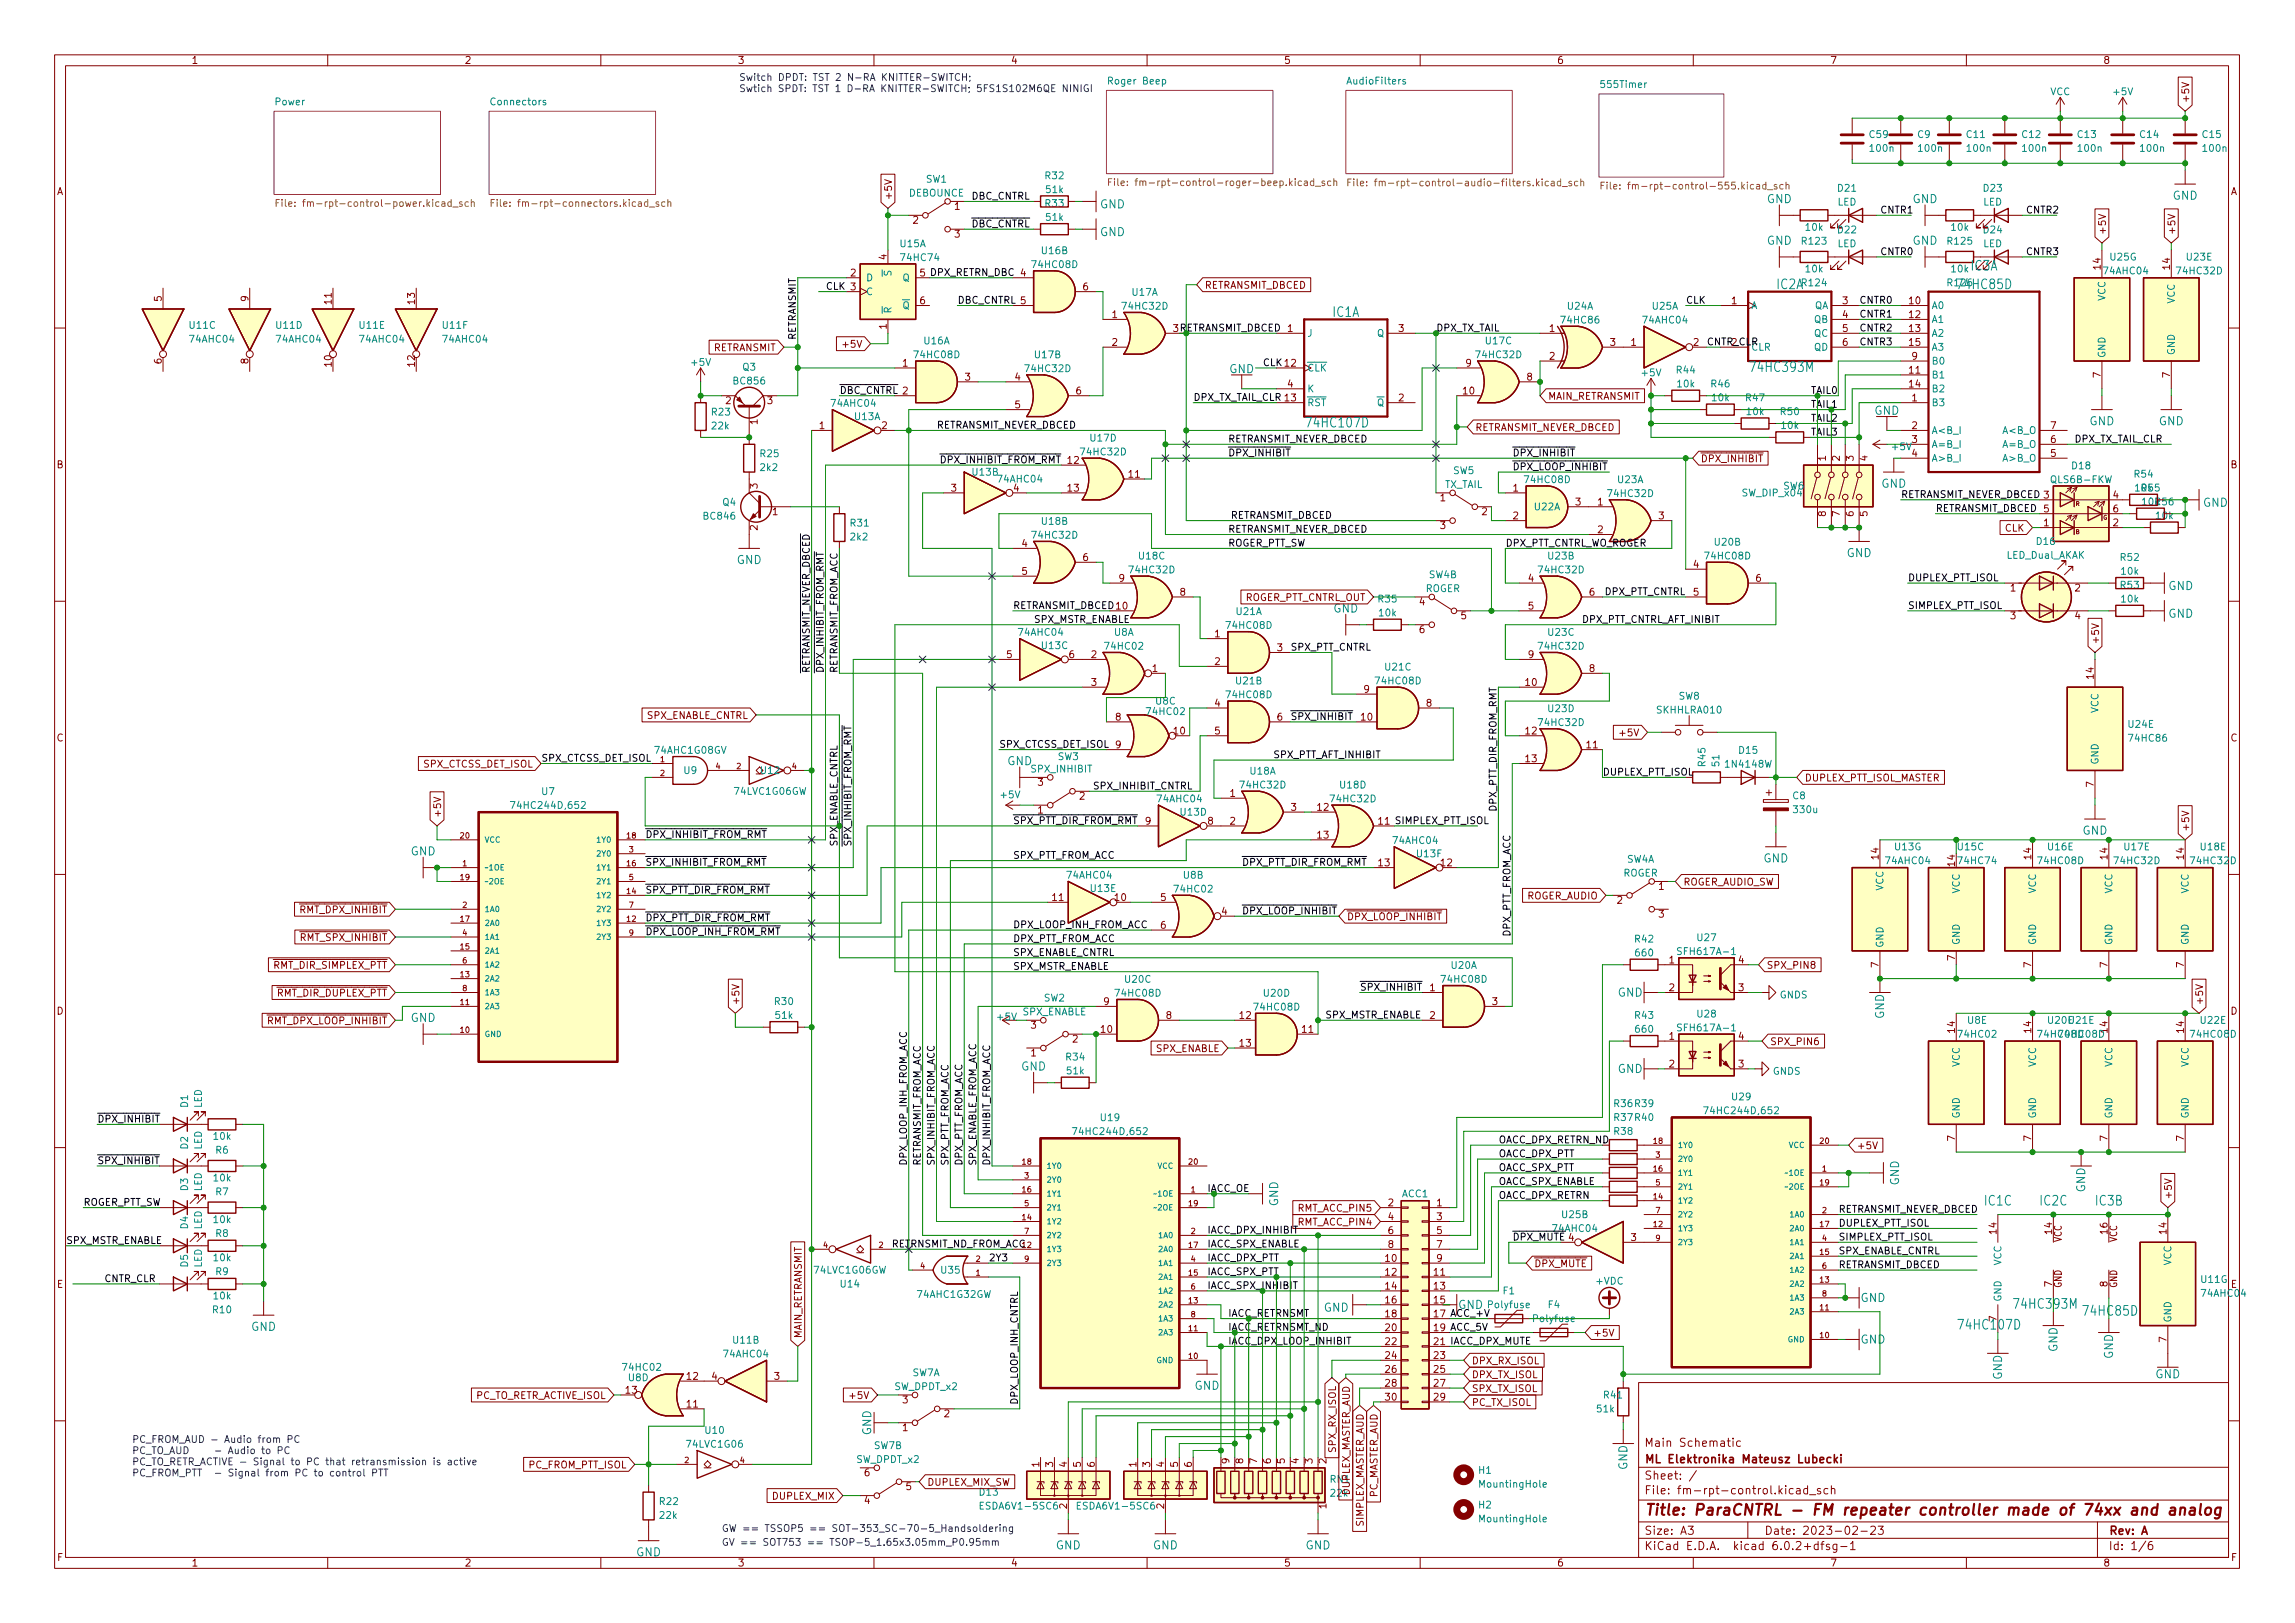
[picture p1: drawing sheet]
<svg xmlns="http://www.w3.org/2000/svg" width="420mm" height="297mm" viewBox="0 0 420 297" stroke-linecap="round" stroke-linejoin="round" font-family="sans-serif">
<defs><g id="words">
<text font-size="2.8" fill="#840000" x="301" y="277.3">Title: ParaCNTRL - FM repeater controller made of 74xx and analog</text>
<g font-size="2.5" fill="#008484">
<text x="325.3" y="52.9">IC2A</text>
<text x="358.6" y="52.9">74HC85D</text>
<text x="360.8" y="49.5">IC3A</text>
<text x="244" y="58">IC1A</text>
<text x="320.8" y="68.1">74HC393M</text>
<text x="239.6" y="78.2">74HC107D</text>
<text x="363.4" y="220.6">IC1C</text>
<text x="373.5" y="220.6">IC2C</text>
<text x="383.7" y="220.6">IC3B</text>
<text x="358.9" y="243.3">74HC107D</text>
<text x="381.7" y="240.8">74HC85D</text>
</g>
<text font-size="2.5" fill="#008400" x="369.1" y="239.5">74HC393M</text>
<g font-size="2.1" fill="#008484">
<text x="201.4" y="38.1">GND</text>
<text x="323.4" y="37.2">GND</text>
<text x="350.1" y="37.2">GND</text>
<text x="397.7" y="36.5">GND</text>
<text x="201.4" y="43.2">GND</text>
<text x="323.4" y="44.8">GND</text>
<text x="350.1" y="44.8">GND</text>
<text x="225" y="68.3">GND</text>
<text x="343.1" y="75.9">GND</text>
<text x="382.5" y="77.8">GND</text>
<text x="395.2" y="77.8">GND</text>
<text x="344.4" y="89.3">GND</text>
<text x="403.3" y="92.7">GND</text>
<text x="338" y="102">GND</text>
<text x="134.8" y="103.2">GND</text>
<text x="396.9" y="108">GND</text>
<text x="396.9" y="113.1">GND</text>
<text x="184.4" y="140">GND</text>
<text x="381.2" y="152.8">GND</text>
<text x="75.2" y="156.5">GND</text>
<text x="322.8" y="157.8">GND</text>
<text x="296.1" y="182.4">GND</text>
<text x="75.2" y="187">GND</text>
<text x="344.9" y="186.5" transform="rotate(-90 344.9 186.5)">GND</text>
<text x="186.9" y="195.9">GND</text>
<text x="296.1" y="196.4">GND</text>
<text x="234" y="220.8" transform="rotate(-90 234 220.8)">GND</text>
<text x="347.7" y="217" transform="rotate(-90 347.7 217)">GND</text>
<text x="381.7" y="218.3" transform="rotate(-90 381.7 218.3)">GND</text>
<text x="266.9" y="239.5">GND</text>
<text x="340.6" y="238.3">GND</text>
<text x="45.9" y="243.6">GND</text>
<text x="242.3" y="240.1">GND</text>
<text x="340.6" y="245.9">GND</text>
<text x="376.7" y="247.5" transform="rotate(-90 376.7 247.5)">GND</text>
<text x="386.8" y="248.7" transform="rotate(-90 386.8 248.7)">GND</text>
<text x="218.7" y="254.4">GND</text>
<text x="366.5" y="252.5" transform="rotate(-90 366.5 252.5)">GND</text>
<text x="394.6" y="252.2">GND</text>
<text x="159.5" y="262.7" transform="rotate(-90 159.5 262.7)">GND</text>
<text x="297.9" y="269.1" transform="rotate(-90 297.9 269.1)">GND</text>
<text x="116.4" y="284.8">GND</text>
<text x="193.3" y="283.6">GND</text>
<text x="211" y="283.6">GND</text>
<text x="239" y="283.6">GND</text>
</g>
<g font-size="2.1" fill="#840000">
<text x="244.1" y="112.1">GND</text>
<text x="301" y="267.8">ML Elektronika Mateusz Lubecki</text>
<text x="301" y="264.8">Main Schematic</text>
<text x="301" y="273.5">File: fm-rpt-control.kicad_sch</text>
<text x="301" y="270.8">Sheet: /</text>
<text x="301" y="280.9">Size: A3</text>
<text x="323" y="280.9">Date: 2023-02-23</text>
<text x="386" y="280.9">Rev: A</text>
<text x="301" y="283.7">KiCad E.D.A. kicad 6.0.2+dfsg-1</text>
<text x="386" y="283.7">Id: 1/6</text>
</g>
<g font-size="1.8" fill="#840000">
<text x="35" y="11.7">1</text>
<text x="85" y="11.7">2</text>
<text x="135" y="11.7">3</text>
<text x="185" y="11.7">4</text>
<text x="235" y="11.7">5</text>
<text x="285" y="11.7">6</text>
<text x="335" y="11.7">7</text>
<text x="385" y="11.7">8</text>
<text x="400.8" y="18.9" transform="rotate(-90 400.8 18.9)">+5V</text>
<text x="10.3" y="35.7">A</text>
<text x="408.3" y="35.7">A</text>
<text x="163.3" y="36.7" transform="rotate(-90 163.3 36.7)">+5V</text>
<text x="167.1" y="40.9">2</text>
<text x="174.8" y="38.4">1</text>
<text x="162.3" y="47.5" transform="rotate(-90 162.3 47.5)">4</text>
<text x="174.8" y="43.5">3</text>
<text x="385.5" y="43.1" transform="rotate(-90 385.5 43.1)">+5V</text>
<text x="398.2" y="43.1" transform="rotate(-90 398.2 43.1)">+5V</text>
<text x="155.7" y="50.6">2</text>
<text x="198.3" y="53.1">6</text>
<text x="220.5" y="52.8">RETRANSMIT_DBCED</text>
<text x="384.6" y="49.3" transform="rotate(-90 384.6 49.3)">14</text>
<text x="397.3" y="49.3" transform="rotate(-90 397.3 49.3)">14</text>
<text x="29.6" y="55.1" transform="rotate(-90 29.6 55.1)">5</text>
<text x="45.5" y="55.1" transform="rotate(-90 45.5 55.1)">9</text>
<text x="60.7" y="55.6" transform="rotate(-90 60.7 55.6)">11</text>
<text x="75.9" y="55.6" transform="rotate(-90 75.9 55.6)">13</text>
<text x="168.4" y="55.7">6</text>
<text x="203.6" y="58.2">1</text>
<text x="317" y="55.7">1</text>
<text x="337.3" y="55.7">3</text>
<text x="337.3" y="58.2">4</text>
<text x="349.5" y="55.7">10</text>
<text x="349.5" y="58.2">12</text>
<text x="130.5" y="64.3">RETRANSMIT</text>
<text x="154.8" y="63.6">+5V</text>
<text x="162.3" y="60.2" transform="rotate(-90 162.3 60.2)">1</text>
<text x="203.6" y="63.3">2</text>
<text x="256" y="60.7">3</text>
<text x="283.7" y="60.7">1</text>
<text x="283.7" y="65.8">2</text>
<text x="294.8" y="63.3">3</text>
<text x="298.6" y="63.3">1</text>
<text x="310" y="63.3">2</text>
<text x="337.3" y="60.7">5</text>
<text x="337.3" y="63.3">6</text>
<text x="349.5" y="60.7">13</text>
<text x="349.5" y="63.3">15</text>
<text x="350" y="65.8">9</text>
<text x="29.6" y="66.6" transform="rotate(-90 29.6 66.6)">6</text>
<text x="45.5" y="66.6" transform="rotate(-90 45.5 66.6)">8</text>
<text x="60.7" y="67.1" transform="rotate(-90 60.7 67.1)">10</text>
<text x="75.9" y="67.1" transform="rotate(-90 75.9 67.1)">12</text>
<text x="165.2" y="67.1">1</text>
<text x="176.7" y="69.6">3</text>
<text x="185.8" y="69.6">4</text>
<text x="235.7" y="70.9">4</text>
<text x="268.4" y="67.1">9</text>
<text x="279.5" y="69.6">8</text>
<text x="349.5" y="68.4">11</text>
<text x="349.5" y="70.9">14</text>
<text x="384.6" y="69.1" transform="rotate(-90 384.6 69.1)">7</text>
<text x="397.3" y="69.1" transform="rotate(-90 397.3 69.1)">7</text>
<text x="132.9" y="74">2</text>
<text x="138.7" y="77.7" transform="rotate(-90 138.7 77.7)">1</text>
<text x="140.5" y="74">3</text>
<text x="165.2" y="72.2">2</text>
<text x="185.8" y="74.7">5</text>
<text x="197" y="72.2">6</text>
<text x="256" y="73.4">2</text>
<text x="267.9" y="72.2">10</text>
<text x="283.4" y="73.2">MAIN_RETRANSMIT</text>
<text x="350" y="73.4">1</text>
<text x="150" y="78.5">1</text>
<text x="161.4" y="78.5">2</text>
<text x="270" y="78.9">RETRANSMIT_NEVER_DBCED</text>
<text x="350" y="78.5">2</text>
<text x="350" y="81.1">3</text>
<text x="350" y="83.6">4</text>
<text x="375.4" y="83.6">5</text>
<text x="375.4" y="81.1">6</text>
<text x="375.4" y="78.5">7</text>
<text x="10.3" y="85.7">B</text>
<text x="138.7" y="89.4" transform="rotate(-90 138.7 89.4)">3</text>
<text x="174.1" y="90">3</text>
<text x="185.6" y="90">4</text>
<text x="195.5" y="90">13</text>
<text x="206.7" y="87.4">11</text>
<text x="277" y="90">1</text>
<text x="311.3" y="84.6">~{DPX_INHIBIT}</text>
<text x="334.3" y="84.3" transform="rotate(-90 334.3 84.3)">1</text>
<text x="336.8" y="84.3" transform="rotate(-90 336.8 84.3)">2</text>
<text x="339.3" y="84.3" transform="rotate(-90 339.3 84.3)">3</text>
<text x="341.9" y="84.3" transform="rotate(-90 341.9 84.3)">4</text>
<text x="408.3" y="85.7">B</text>
<text x="141.4" y="94.3">1</text>
<text x="263.7" y="91.7">1</text>
<text x="271.3" y="94.3">2</text>
<text x="277" y="95">2</text>
<text x="288.4" y="92.5">3</text>
<text x="292.5" y="92.5">1</text>
<text x="303.7" y="95">3</text>
<text x="334.3" y="94.5" transform="rotate(-90 334.3 94.5)">8</text>
<text x="336.8" y="94.5" transform="rotate(-90 336.8 94.5)">7</text>
<text x="339.3" y="94.5" transform="rotate(-90 339.3 94.5)">6</text>
<text x="341.9" y="94.5" transform="rotate(-90 341.9 94.5)">5</text>
<text x="386.9" y="91.2">4</text>
<text x="386.9" y="93.8">6</text>
<text x="392.2" y="92.5">10kR56</text>
<text x="394.8" y="95">10k</text>
<text x="138.7" y="97" transform="rotate(-90 138.7 97)">2</text>
<text x="187.1" y="100.1">4</text>
<text x="263.7" y="96.8">3</text>
<text x="292.5" y="97.6">2</text>
<text x="367" y="97.3">CLK</text>
<text x="374.2" y="96.3">1</text>
<text x="386.9" y="96.3">2</text>
<text x="187.1" y="105.2">5</text>
<text x="198.3" y="102.7">6</text>
<text x="204.9" y="106.5">9</text>
<text x="279.8" y="106.5">4</text>
<text x="310" y="103.9">4</text>
<text x="321.5" y="106.5">6</text>
<text x="216" y="109">8</text>
<text x="227.5" y="110">ROGER_PTT_CNTRL_OUT</text>
<text x="259.9" y="110.8">4</text>
<text x="267.5" y="113.3">5</text>
<text x="279.8" y="111.5">5</text>
<text x="291" y="109">6</text>
<text x="310" y="109">5</text>
<text x="368.1" y="108.2">1</text>
<text x="368.1" y="113.3">3</text>
<text x="379.9" y="108.2">2</text>
<text x="379.9" y="113.3">4</text>
<text x="222.4" y="116.6">1</text>
<text x="233.8" y="119.2">3</text>
<text x="259.9" y="115.9">6</text>
<text x="384.3" y="118" transform="rotate(-90 384.3 118)">+5V</text>
<text x="184.3" y="120.4">5</text>
<text x="195.7" y="120.4">6</text>
<text x="199.8" y="120.4">2</text>
<text x="199.8" y="125.5">3</text>
<text x="211" y="123">1</text>
<text x="222.4" y="121.7">2</text>
<text x="279.3" y="125.5">10</text>
<text x="279.8" y="120.4">9</text>
<text x="291" y="123">8</text>
<text x="383.3" y="124.2" transform="rotate(-90 383.3 124.2)">14</text>
<text x="118.2" y="131.6">SPX_ENABLE_CNTRL</text>
<text x="204.2" y="131.9">8</text>
<text x="222.4" y="129.3">4</text>
<text x="233.8" y="131.9">6</text>
<text x="249.7" y="126.8">9</text>
<text x="261.1" y="129.3">8</text>
<text x="10.3" y="135.7">C</text>
<text x="204.2" y="136.9">9</text>
<text x="214.9" y="134.4">10</text>
<text x="222.4" y="134.4">5</text>
<text x="279.3" y="134.4">12</text>
<text x="290.5" y="136.9">11</text>
<text x="297" y="134.7">+5V</text>
<text x="408.3" y="135.7">C</text>
<text x="77.5" y="140.5">SPX_CTCSS_DET_ISOL</text>
<text x="190" y="143.8">3</text>
<text x="279.3" y="139.5">13</text>
<text x="330.4" y="143">DUPLEX_PTT_ISOL_MASTER</text>
<text x="80.7" y="149.7" transform="rotate(-90 80.7 149.7)">+5V</text>
<text x="190" y="148.9">1</text>
<text x="197.6" y="146.3">2</text>
<text x="225.2" y="145.8">1</text>
<text x="236.4" y="148.4">3</text>
<text x="241.2" y="148.4">12</text>
<text x="383.3" y="144" transform="rotate(-90 383.3 144)">7</text>
<text x="209.7" y="150.9">9</text>
<text x="221.1" y="150.9">8</text>
<text x="225.2" y="150.9">2</text>
<text x="241.2" y="153.5">13</text>
<text x="400.8" y="152.3" transform="rotate(-90 400.8 152.3)">+5V</text>
<text x="263.8" y="158.5">12</text>
<text x="343.9" y="157.2" transform="rotate(-90 343.9 157.2)">14</text>
<text x="357.9" y="158.5" transform="rotate(-90 357.9 158.5)">14</text>
<text x="371.9" y="157.2" transform="rotate(-90 371.9 157.2)">14</text>
<text x="385.8" y="157.2" transform="rotate(-90 385.8 157.2)">14</text>
<text x="399.8" y="157.2" transform="rotate(-90 399.8 157.2)">14</text>
<text x="53.8" y="167.1">~{RMT_DPX_INHIBIT}</text>
<text x="192.7" y="164.9">11</text>
<text x="204.1" y="164.9">10</text>
<text x="212.5" y="164.9">5</text>
<text x="223.7" y="167.4">4</text>
<text x="279.4" y="164.6">ROGER_AUDIO</text>
<text x="296.1" y="165.4">2</text>
<text x="303.7" y="162.9">1</text>
<text x="303.7" y="167.9">3</text>
<text x="308.1" y="162.1">ROGER_AUDIO_SW</text>
<text x="53.9" y="172.2">~{RMT_SPX_INHIBIT}</text>
<text x="212.5" y="170">6</text>
<text x="246.5" y="168.4">~{DPX_LOOP_INHIBIT}</text>
<text x="48.7" y="177.3">~{RMT_DIR_SIMPLEX_PTT}</text>
<text x="305.6" y="176.3">1</text>
<text x="318.3" y="176.3">4</text>
<text x="323.4" y="177.3">SPX_PIN8</text>
<text x="343.9" y="177.1" transform="rotate(-90 343.9 177.1)">7</text>
<text x="357.9" y="175.8" transform="rotate(-90 357.9 175.8)">7</text>
<text x="371.9" y="177.1" transform="rotate(-90 371.9 177.1)">7</text>
<text x="385.8" y="177.1" transform="rotate(-90 385.8 177.1)">7</text>
<text x="399.8" y="177.1" transform="rotate(-90 399.8 177.1)">7</text>
<text x="10.3" y="185.7">D</text>
<text x="49.2" y="182.4">~{RMT_DIR_DUPLEX_PTT}</text>
<text x="135.3" y="184" transform="rotate(-90 135.3 184)">+5V</text>
<text x="202.1" y="183.9">9</text>
<text x="273.2" y="183.9">3</text>
<text x="305.6" y="181.4">2</text>
<text x="318.3" y="181.4">3</text>
<text x="403.3" y="184" transform="rotate(-90 403.3 184)">+5V</text>
<text x="408.3" y="185.7">D</text>
<text x="47.8" y="187.5">~{RMT_DPX_LOOP_INHIBIT}</text>
<text x="188.7" y="188.3">3</text>
<text x="196.4" y="190.8">2</text>
<text x="201.6" y="189">10</text>
<text x="213.5" y="186.5">8</text>
<text x="227" y="186.5">12</text>
<text x="227" y="191.6">13</text>
<text x="238.4" y="189">11</text>
<text x="261.8" y="186.5">2</text>
<text x="305.6" y="190.3">1</text>
<text x="318.3" y="190.3">4</text>
<text x="324" y="191.3">SPX_PIN6</text>
<text x="357.9" y="189" transform="rotate(-90 357.9 189)">14</text>
<text x="371.9" y="189" transform="rotate(-90 371.9 189)">14</text>
<text x="385.8" y="189" transform="rotate(-90 385.8 189)">14</text>
<text x="399.8" y="189" transform="rotate(-90 399.8 189)">14</text>
<text x="188.7" y="193.3">1</text>
<text x="211.6" y="192.5">SPX_ENABLE</text>
<text x="305.6" y="195.4">2</text>
<text x="318.3" y="195.4">3</text>
<text x="357.9" y="208.8" transform="rotate(-90 357.9 208.8)">7</text>
<text x="371.9" y="208.8" transform="rotate(-90 371.9 208.8)">7</text>
<text x="385.8" y="208.8" transform="rotate(-90 385.8 208.8)">7</text>
<text x="399.8" y="208.8" transform="rotate(-90 399.8 208.8)">7</text>
<text x="339.9" y="210.3">+5V</text>
<text x="237.7" y="221.7">RMT_ACC_PIN5</text>
<text x="254.1" y="220.8">2</text>
<text x="263" y="220.8">1</text>
<text x="397.6" y="219.6" transform="rotate(-90 397.6 219.6)">+5V</text>
<text x="237.7" y="224.3">RMT_ACC_PIN4</text>
<text x="254.1" y="223.3">4</text>
<text x="254.1" y="225.8">6</text>
<text x="263" y="223.3">3</text>
<text x="263" y="225.8">5</text>
<text x="287.2" y="227.1">4</text>
<text x="298.6" y="227.1">3</text>
<text x="365.5" y="225.8" transform="rotate(-90 365.5 225.8)">14</text>
<text x="375.7" y="225.8" transform="rotate(-90 375.7 225.8)">14</text>
<text x="377.4" y="227.3" transform="rotate(-90 377.4 227.3)">VCC</text>
<text x="385.8" y="225.8" transform="rotate(-90 385.8 225.8)">16</text>
<text x="387.6" y="227.3" transform="rotate(-90 387.6 227.3)">VCC</text>
<text x="396.6" y="225.8" transform="rotate(-90 396.6 225.8)">14</text>
<text x="253.7" y="230.9">10</text>
<text x="253.7" y="233.5">12</text>
<text x="254.1" y="228.4">8</text>
<text x="262.5" y="233.5">11</text>
<text x="263" y="228.4">7</text>
<text x="263" y="230.9">9</text>
<text x="280.8" y="231.9">~{DPX_MUTE}</text>
<text x="10.4" y="235.7">E</text>
<text x="253.7" y="236">14</text>
<text x="253.7" y="238.5">16</text>
<text x="262.5" y="236">13</text>
<text x="262.5" y="238.5">15</text>
<text x="375.7" y="235.5" transform="rotate(-90 375.7 235.5)">7</text>
<text x="377.4" y="235.7" transform="rotate(-90 377.4 235.7)">GND</text>
<text x="385.8" y="235.5" transform="rotate(-90 385.8 235.5)">8</text>
<text x="387.6" y="235.7" transform="rotate(-90 387.6 235.7)">GND</text>
<text x="408.4" y="235.7">E</text>
<text x="146.8" y="245" transform="rotate(-90 146.8 245)">MAIN_RETRANSMIT</text>
<text x="253.7" y="241.1">18</text>
<text x="253.7" y="243.6">20</text>
<text x="291.6" y="244.6">+5V</text>
<text x="365.5" y="241.8" transform="rotate(-90 365.5 241.8)">7</text>
<text x="396.6" y="245.6" transform="rotate(-90 396.6 245.6)">7</text>
<text x="253.7" y="246.2">22</text>
<text x="253.7" y="248.7">24</text>
<text x="253.7" y="251.2">26</text>
<text x="262.5" y="248.7">23</text>
<text x="262.5" y="251.2">25</text>
<text x="269.4" y="249.7">DPX_RX_ISOL</text>
<text x="86.7" y="256">PC_TO_RETR_ACTIVE_ISOL</text>
<text x="114.6" y="255.1">13</text>
<text x="125.8" y="257.6">11</text>
<text x="125.8" y="252.5">12</text>
<text x="130.3" y="252.5">4</text>
<text x="141.7" y="252.5">3</text>
<text x="156" y="256">+5V</text>
<text x="165.2" y="256.8">3</text>
<text x="253.7" y="253.8">28</text>
<text x="253.7" y="256.3">30</text>
<text x="262.5" y="253.8">27</text>
<text x="262.5" y="256.3">29</text>
<text x="269.4" y="252.2">DPX_TX_ISOL</text>
<text x="269.4" y="254.8">SPX_TX_ISOL</text>
<text x="269.4" y="257.3">PC_TX_ISOL</text>
<text x="165.2" y="261.9">1</text>
<text x="172.9" y="259.4">2</text>
<text x="96.7" y="268.7">PC_FROM_PTT_ISOL</text>
<text x="190.2" y="268.5" transform="rotate(-90 190.2 268.5)">1</text>
<text x="192.8" y="268.5" transform="rotate(-90 192.8 268.5)">3</text>
<text x="195.3" y="268.5" transform="rotate(-90 195.3 268.5)">4</text>
<text x="197.9" y="268.5" transform="rotate(-90 197.9 268.5)">5</text>
<text x="200.4" y="268.5" transform="rotate(-90 200.4 268.5)">6</text>
<text x="208" y="268.5" transform="rotate(-90 208 268.5)">1</text>
<text x="210.6" y="268.5" transform="rotate(-90 210.6 268.5)">3</text>
<text x="213.1" y="268.5" transform="rotate(-90 213.1 268.5)">4</text>
<text x="215.6" y="268.5" transform="rotate(-90 215.6 268.5)">5</text>
<text x="218.2" y="268.5" transform="rotate(-90 218.2 268.5)">6</text>
<text x="225" y="267.9" transform="rotate(-90 225 267.9)">9</text>
<text x="227.6" y="267.9" transform="rotate(-90 227.6 267.9)">8</text>
<text x="230.1" y="267.9" transform="rotate(-90 230.1 267.9)">7</text>
<text x="232.7" y="267.9" transform="rotate(-90 232.7 267.9)">6</text>
<text x="235.2" y="267.9" transform="rotate(-90 235.2 267.9)">5</text>
<text x="237.7" y="267.9" transform="rotate(-90 237.7 267.9)">4</text>
<text x="240.3" y="267.9" transform="rotate(-90 240.3 267.9)">3</text>
<text x="242.8" y="267.9" transform="rotate(-90 242.8 267.9)">2</text>
<text x="244.6" y="265.7" transform="rotate(-90 244.6 265.7)">SPX_RX_ISOL</text>
<text x="141.6" y="274.4">DUPLEX_MIX</text>
<text x="158.3" y="275.2">4</text>
<text x="158.3" y="270.2">6</text>
<text x="165.9" y="272.7">5</text>
<text x="169.7" y="271.9">DUPLEX_MIX_SW</text>
<text x="179.4" y="273.7">D13</text>
<text x="197.2" y="273.7">D14</text>
<text x="243.5" y="271.4">RN1</text>
<text x="243.7" y="273.9">22k</text>
<text x="247.1" y="274" transform="rotate(-90 247.1 274)">DUPLEX_MASTER_AUD</text>
<text x="252.2" y="274.4" transform="rotate(-90 252.2 274.4)">PC_MASTER_AUD</text>
<text x="195.3" y="276.1" transform="rotate(-90 195.3 276.1)">2</text>
<text x="213.1" y="276.1" transform="rotate(-90 213.1 276.1)">2</text>
<text x="242.8" y="276.1" transform="rotate(-90 242.8 276.1)">1</text>
<text x="249.6" y="279.7" transform="rotate(-90 249.6 279.7)">SIMPLEX_MASTER_AUD</text>
<text x="10.4" y="285.7">F</text>
<text x="35" y="286.7">1</text>
<text x="85" y="286.7">2</text>
<text x="135" y="286.7">3</text>
<text x="185" y="286.7">4</text>
<text x="235" y="286.7">5</text>
<text x="285" y="286.7">6</text>
<text x="335" y="286.7">7</text>
<text x="385" y="286.7">8</text>
<text x="408.4" y="285.7">F</text>
</g>
<g font-size="1.8" fill="#0000c2">
<text x="135.3" y="14.8">Switch DPDT: TST 2 N-RA KNITTER-SWITCH;</text>
<text x="135.3" y="16.8">Swtich SPDT: TST 1 D-RA KNITTER-SWITCH; 5FS1S102M6QE NINIGI</text>
<text x="24.1" y="264.1">PC_FROM_AUD - Audio from PC</text>
<text x="24.1" y="266.1">PC_TO_AUD - Audio to PC</text>
<text x="24.1" y="268.2">PC_TO_RETR_ACTIVE - Signal to PC that retransmission is active</text>
<text x="24.1" y="270.2">PC_FROM_PTT - Signal from PC to control PTT</text>
<text x="132.1" y="280.4">GW == TSSOP5 == SOT-353_SC-70-5_Handsoldering</text>
<text x="132.1" y="282.9">GV == SOT753 == TSOP-5_1.65x3.05mm_P0.95mm</text>
</g>
<g font-size="1.8" fill="#008484">
<text x="203.2" y="15.4">Roger Beep</text>
<text x="246.9" y="15.4">AudioFilters</text>
<text x="293.3" y="16.1">555Timer</text>
<text x="375.3" y="17.4">VCC</text>
<text x="387" y="17.4">+5V</text>
<text x="50.4" y="19.3">Power</text>
<text x="90" y="19.3">Connectors</text>
<text x="342.3" y="25.2">C59</text>
<text x="342.5" y="27.8">100n</text>
<text x="351.1" y="25.2">C9</text>
<text x="351.4" y="27.8">100n</text>
<text x="360.1" y="25.2">C11</text>
<text x="360.2" y="27.8">100n</text>
<text x="370.3" y="25.2">C12</text>
<text x="370.4" y="27.8">100n</text>
<text x="380.4" y="25.2">C13</text>
<text x="380.6" y="27.8">100n</text>
<text x="391.8" y="25.2">C14</text>
<text x="392" y="27.8">100n</text>
<text x="403.3" y="25.2">C15</text>
<text x="403.4" y="27.8">100n</text>
<text x="166.4" y="36">DEBOUNCE</text>
<text x="169.5" y="33.4">SW1</text>
<text x="191.4" y="32.8">R32</text>
<text x="191.6" y="35.3">51k</text>
<text x="336.5" y="35.1">D21</text>
<text x="363.2" y="35.1">D23</text>
<text x="191.4" y="37.9">R33</text>
<text x="191.6" y="40.4">51k</text>
<text x="336.4" y="37.6">LED</text>
<text x="363" y="37.6">LED</text>
<text x="164.8" y="45.2">U15A</text>
<text x="165.1" y="47.8">74HC74</text>
<text x="190.8" y="46.5">U16B</text>
<text x="330" y="44.8">R123</text>
<text x="330.6" y="42.2">10k</text>
<text x="336.4" y="45.2">LED</text>
<text x="336.5" y="42.7">D22</text>
<text x="356.7" y="44.8">R125</text>
<text x="357.3" y="42.2">10k</text>
<text x="363" y="45.2">LED</text>
<text x="363.2" y="42.7">D24</text>
<text x="386.4" y="47.7">U25G</text>
<text x="400.4" y="47.7">U23E</text>
<text x="158.5" y="51.5">D</text>
<text x="165.2" y="51.5">Q</text>
<text x="189.2" y="49">74HC08D</text>
<text x="330" y="52.4">R124</text>
<text x="330.6" y="49.8">10k</text>
<text x="356.7" y="52.4">R126</text>
<text x="357.3" y="49.8">10k</text>
<text x="385.3" y="50.2">74AHC04</text>
<text x="398.7" y="50.2">74HC32D</text>
<text x="158.5" y="54">C</text>
<text x="163.2" y="57.4" transform="rotate(-90 163.2 57.4)">~{R}</text>
<text x="163.9" y="56.6">~{Q}</text>
<text x="205.7" y="56.7">74HC32D</text>
<text x="207.3" y="54.1">U17A</text>
<text x="286" y="59.2">74HC86</text>
<text x="287" y="56.7">U24A</text>
<text x="300.9" y="59.2">74AHC04</text>
<text x="302.5" y="56.7">U25A</text>
<text x="320.5" y="56.6">A</text>
<text x="332.1" y="56.6">QA</text>
<text x="332.1" y="59.1">QB</text>
<text x="353.6" y="56.6">A0</text>
<text x="353.6" y="59.1">A1</text>
<text x="385.4" y="55.1" transform="rotate(-90 385.4 55.1)">VCC</text>
<text x="398.1" y="55.6" transform="rotate(-90 398.1 55.6)">VCC</text>
<text x="34.7" y="60.2">U11C</text>
<text x="34.9" y="62.7">74AHC04</text>
<text x="50.6" y="60.2">U11D</text>
<text x="50.8" y="62.7">74AHC04</text>
<text x="65.8" y="60.2">U11E</text>
<text x="66" y="62.7">74AHC04</text>
<text x="81.1" y="60.2">U11F</text>
<text x="81.2" y="62.7">74AHC04</text>
<text x="167.6" y="65.5">74HC08D</text>
<text x="169.2" y="63">U16A</text>
<text x="189.5" y="65.6">U17B</text>
<text x="239.3" y="61.6">J</text>
<text x="252.1" y="61.6">Q</text>
<text x="270.4" y="65.5">74HC32D</text>
<text x="272.1" y="63">U17C</text>
<text x="332.1" y="61.6">QC</text>
<text x="332.1" y="64.2">QD</text>
<text x="353.6" y="61.6">A2</text>
<text x="353.6" y="64.2">A3</text>
<text x="385.4" y="65.6" transform="rotate(-90 385.4 65.6)">GND</text>
<text x="398.1" y="65.1" transform="rotate(-90 398.1 65.1)">GND</text>
<text x="126.7" y="66.9">+5V</text>
<text x="134.4" y="70.3">BC856</text>
<text x="136" y="67.8">Q3</text>
<text x="187.9" y="68.1">74HC32D</text>
<text x="239.3" y="68">~{CLK}</text>
<text x="239.3" y="71.8">K</text>
<text x="300.7" y="68.9">+5V</text>
<text x="307" y="68.3">R44</text>
<text x="307.1" y="70.9">10k</text>
<text x="313.3" y="70.9">R46</text>
<text x="353.6" y="69.3">B1</text>
<text x="353.6" y="71.8">B2</text>
<text x="353.6" y="66.7">B0</text>
<text x="130.4" y="76">R23</text>
<text x="152.3" y="74.4">74AHC04</text>
<text x="156.5" y="76.9">U13A</text>
<text x="239.3" y="74.3">~{RST}</text>
<text x="250.7" y="74.3">~{Q}</text>
<text x="313.5" y="73.4">10k</text>
<text x="319.7" y="73.4">R47</text>
<text x="319.8" y="76">10k</text>
<text x="326" y="76">R50</text>
<text x="353.6" y="74.3">B3</text>
<text x="130.4" y="78.6">22k</text>
<text x="139.2" y="83.7">R25</text>
<text x="198" y="83.3">74HC32D</text>
<text x="199.7" y="80.8">U17D</text>
<text x="326.2" y="78.5">10k</text>
<text x="346.5" y="82.4">+5V</text>
<text x="353.6" y="79.4">A&lt;B_I</text>
<text x="353.6" y="82">A=B_I</text>
<text x="366.9" y="82">A=B_O</text>
<text x="366.9" y="79.4">A&lt;B_O</text>
<text x="139.3" y="86.2">2k2</text>
<text x="178.1" y="87">U13B</text>
<text x="182.8" y="88.3">74AHC04</text>
<text x="264.4" y="89.3">TX_TAIL</text>
<text x="266.1" y="86.8">SW5</text>
<text x="279.3" y="88.4">74HC08D</text>
<text x="296.2" y="88.4">U23A</text>
<text x="326.5" y="89.6">SW6</text>
<text x="353.6" y="84.5">A&gt;B_I</text>
<text x="366.9" y="84.5">A&gt;B_O</text>
<text x="375.7" y="88.4">QLS6B-FKW</text>
<text x="379.4" y="85.9">D18</text>
<text x="390.8" y="87.4">R54</text>
<text x="391" y="89.9">10k</text>
<text x="128.9" y="95.1">BC846</text>
<text x="132.3" y="92.5">Q4</text>
<text x="280.9" y="93.4">U22A</text>
<text x="294.6" y="90.9">74HC32D</text>
<text x="319.1" y="90.8">SW_DIP_x04</text>
<text x="155.8" y="96.4">R31</text>
<text x="155.8" y="98.9">2k2</text>
<text x="189.2" y="98.6">74HC32D</text>
<text x="190.8" y="96">U18B</text>
<text x="314" y="99.8">U20B</text>
<text x="372.9" y="99.7">D16</text>
<text x="206.9" y="104.9">74HC32D</text>
<text x="208.6" y="102.4">U18C</text>
<text x="261.6" y="105.8">SW4B</text>
<text x="281.9" y="104.9">74HC32D</text>
<text x="283.5" y="102.4">U23B</text>
<text x="312.3" y="102.4">74HC08D</text>
<text x="367.3" y="102.3">LED_Dual_AKAK</text>
<text x="388.3" y="107.7">R53</text>
<text x="388.3" y="102.6">R52</text>
<text x="388.4" y="105.2">10k</text>
<text x="226.3" y="112.5">U21A</text>
<text x="252.4" y="110.3">R35</text>
<text x="252.5" y="112.8">10k</text>
<text x="260.9" y="108.3">ROGER</text>
<text x="388.4" y="110.3">10k</text>
<text x="186.6" y="116.3">74AHC04</text>
<text x="190.8" y="118.8">U13C</text>
<text x="202.5" y="118.9">74HC02</text>
<text x="204" y="116.4">U8A</text>
<text x="224.7" y="115.1">74HC08D</text>
<text x="281.9" y="118.9">74HC32D</text>
<text x="283.5" y="116.4">U23C</text>
<text x="226.3" y="125.2">U21B</text>
<text x="252" y="125.2">74HC08D</text>
<text x="253.6" y="122.7">U21C</text>
<text x="210.1" y="130.8">74HC02</text>
<text x="211.6" y="128.9">U8C</text>
<text x="224.7" y="127.8">74HC08D</text>
<text x="283.5" y="130.3">U23D</text>
<text x="303.4" y="130.6">SKHHLRA010</text>
<text x="307.3" y="128">SW8</text>
<text x="384.2" y="130.5" transform="rotate(-90 384.2 130.5)">VCC</text>
<text x="120" y="137.9">74AHC1G08GV</text>
<text x="281.9" y="132.9">74HC32D</text>
<text x="318.4" y="137.9">D15</text>
<text x="389.7" y="133.2">U24E</text>
<text x="389.9" y="135.7">74HC86</text>
<text x="125.2" y="141.6">U9</text>
<text x="139.3" y="141.6">U12</text>
<text x="188.9" y="141.4">SPX_INHIBIT</text>
<text x="193.7" y="139.1">SW3</text>
<text x="228.9" y="141.8">U18A</text>
<text x="312.2" y="140.2" transform="rotate(-90 312.2 140.2)">R45</text>
<text x="314.8" y="140.2" transform="rotate(-90 314.8 140.2)">51</text>
<text x="316.1" y="140.5">1N4148W</text>
<text x="384.2" y="140" transform="rotate(-90 384.2 140)">GND</text>
<text x="94.2" y="148">74HC244D,652</text>
<text x="99.2" y="145.5">U7</text>
<text x="134.5" y="145.5">74LVC1G06GW</text>
<text x="183.3" y="146.1">+5V</text>
<text x="212" y="146.8">74AHC04</text>
<text x="216.2" y="149.3">U13D</text>
<text x="227.3" y="144.3">74HC32D</text>
<text x="243.8" y="146.8">74HC32D</text>
<text x="245.4" y="144.3">U18D</text>
<text x="328.2" y="146.3">C8</text>
<text x="328.5" y="148.8">330u</text>
<text x="255.2" y="154.4">74AHC04</text>
<text x="346.9" y="155.6">U13G</text>
<text x="375" y="155.6">U16E</text>
<text x="388.9" y="155.6">U17E</text>
<text x="402.9" y="155.6">U18E</text>
<text x="195.5" y="160.8">74AHC04</text>
<text x="216.7" y="160.8">U8B</text>
<text x="259.5" y="156.9">U13F</text>
<text x="297.1" y="160.4">ROGER</text>
<text x="297.8" y="157.9">SW4A</text>
<text x="345.4" y="158.2">74AHC04</text>
<text x="358.7" y="158.1">74HC74</text>
<text x="373.3" y="158.2">74HC08D</text>
<text x="387.3" y="158.2">74HC32D</text>
<text x="401.2" y="158.2">74HC32D</text>
<text x="199.7" y="163.2">U13E</text>
<text x="215.2" y="163.3">74HC02</text>
<text x="344.8" y="163" transform="rotate(-90 344.8 163)">VCC</text>
<text x="358.8" y="163.5" transform="rotate(-90 358.8 163.5)">VCC</text>
<text x="372.7" y="163.5" transform="rotate(-90 372.7 163.5)">VCC</text>
<text x="386.7" y="163.5" transform="rotate(-90 386.7 163.5)">VCC</text>
<text x="400.7" y="163.5" transform="rotate(-90 400.7 163.5)">VCC</text>
<text x="299.4" y="172.5">R42</text>
<text x="310.8" y="172.2">U27</text>
<text x="344.8" y="173.5" transform="rotate(-90 344.8 173.5)">GND</text>
<text x="358.8" y="173" transform="rotate(-90 358.8 173)">GND</text>
<text x="372.7" y="173" transform="rotate(-90 372.7 173)">GND</text>
<text x="386.7" y="173" transform="rotate(-90 386.7 173)">GND</text>
<text x="400.7" y="173" transform="rotate(-90 400.7 173)">GND</text>
<text x="206" y="179.9">U20C</text>
<text x="264.1" y="179.8">74HC08D</text>
<text x="265.7" y="177.3">U20A</text>
<text x="299.5" y="175">660</text>
<text x="307.8" y="174.8">SFH617A-1</text>
<text x="141.9" y="183.9">R30</text>
<text x="187.1" y="185.8">SPX_ENABLE</text>
<text x="191.1" y="183.3">SW2</text>
<text x="204.4" y="182.4">74HC08D</text>
<text x="229.8" y="184.9">74HC08D</text>
<text x="231.4" y="182.4">U20D</text>
<text x="325.8" y="182.7">GNDS</text>
<text x="142" y="186.5">51k</text>
<text x="182.7" y="186.7">+5V</text>
<text x="299.4" y="186.5">R43</text>
<text x="299.5" y="189">660</text>
<text x="307.8" y="188.7">SFH617A-1</text>
<text x="310.8" y="186.2">U28</text>
<text x="358.7" y="189.9">74HC02</text>
<text x="360.2" y="187.4">U8E</text>
<text x="373.3" y="189.9">74HC08D</text>
<text x="375" y="187.4">U20EU21E</text>
<text x="401.2" y="189.9">74HC08D</text>
<text x="402.9" y="187.4">U22E</text>
<text x="195.2" y="194.1">R34</text>
<text x="195.4" y="196.6">51k</text>
<text x="324.5" y="196.7">GNDS</text>
<text x="358.8" y="195.3" transform="rotate(-90 358.8 195.3)">VCC</text>
<text x="372.7" y="195.3" transform="rotate(-90 372.7 195.3)">VCC</text>
<text x="386.7" y="195.3" transform="rotate(-90 386.7 195.3)">VCC</text>
<text x="400.7" y="195.3" transform="rotate(-90 400.7 195.3)">VCC</text>
<text x="34.4" y="202.7" transform="rotate(-90 34.4 202.7)">D1</text>
<text x="36.9" y="202.8" transform="rotate(-90 36.9 202.8)">LED</text>
<text x="295.6" y="202.6">R36 R39</text>
<text x="312.7" y="203.9">74HC244D,652</text>
<text x="317.1" y="201.4">U29</text>
<text x="39.2" y="208.6">10k</text>
<text x="197.1" y="207.7">74HC244D,652</text>
<text x="201.6" y="205.2">U19</text>
<text x="295.6" y="207.7">R38</text>
<text x="295.6" y="205.1">R37 R40</text>
<text x="358.8" y="204.8" transform="rotate(-90 358.8 204.8)">GND</text>
<text x="372.7" y="204.8" transform="rotate(-90 372.7 204.8)">GND</text>
<text x="386.7" y="204.8" transform="rotate(-90 386.7 204.8)">GND</text>
<text x="400.7" y="204.8" transform="rotate(-90 400.7 204.8)">GND</text>
<text x="34.4" y="210.3" transform="rotate(-90 34.4 210.3)">D2</text>
<text x="36.9" y="210.4" transform="rotate(-90 36.9 210.4)">LED</text>
<text x="39.5" y="211.1">R6</text>
<text x="34.4" y="217.9" transform="rotate(-90 34.4 217.9)">D3</text>
<text x="36.9" y="218.1" transform="rotate(-90 36.9 218.1)">LED</text>
<text x="39.2" y="216.2">10k</text>
<text x="39.5" y="218.7">R7</text>
<text x="256.7" y="219.1">ACC1</text>
<text x="34.4" y="224.9" transform="rotate(-90 34.4 224.9)">D4</text>
<text x="36.9" y="225" transform="rotate(-90 36.9 225)">LED</text>
<text x="39.2" y="223.8">10k</text>
<text x="39.5" y="226.4">R8</text>
<text x="286" y="222.9">U25B</text>
<text x="34.4" y="231.9" transform="rotate(-90 34.4 231.9)">D5</text>
<text x="36.9" y="232" transform="rotate(-90 36.9 232)">LED</text>
<text x="39.2" y="230.8">10k</text>
<text x="39.5" y="233.4">R9</text>
<text x="149.1" y="233.1">74LVC1G06GW</text>
<text x="172.4" y="233.1">U35</text>
<text x="366.4" y="231.6" transform="rotate(-90 366.4 231.6)">VCC</text>
<text x="397.5" y="231.6" transform="rotate(-90 397.5 231.6)">VCC</text>
<text x="39.2" y="237.8">10k</text>
<text x="154" y="235.6">U14</text>
<text x="168" y="237.5">74AHC1G32GW</text>
<text x="272.5" y="239.4">Polyfuse</text>
<text x="275.2" y="236.9">F1</text>
<text x="283.4" y="239.4">F4</text>
<text x="292.3" y="235.1">+VDC</text>
<text x="366.4" y="238.3" transform="rotate(-90 366.4 238.3)">GND</text>
<text x="403" y="234.8">U11G</text>
<text x="403.2" y="237.3">74AHC04</text>
<text x="39" y="240.3">R10</text>
<text x="134.3" y="245.9">U11B</text>
<text x="280.8" y="242">Polyfuse</text>
<text x="397.5" y="242.1" transform="rotate(-90 397.5 242.1)">GND</text>
<text x="114.2" y="250.9">74HC02</text>
<text x="132.6" y="248.4">74AHC04</text>
<text x="167" y="251.9">SW7A</text>
<text x="115.1" y="252.8">U8D</text>
<text x="163.7" y="254.4">SW_DPDT_x2</text>
<text x="293.7" y="255.9">R41</text>
<text x="129.2" y="262.4">U10</text>
<text x="292.4" y="258.5">51k</text>
<text x="125.9" y="264.9">74LVC1G06</text>
<text x="156.8" y="267.7">SW_DPDT_x2</text>
<text x="160" y="265.2">SW7B</text>
<text x="270.7" y="269.7">H1</text>
<text x="120.8" y="275.4">R22</text>
<text x="271.1" y="272.2">MountingHole</text>
<text x="120.9" y="278">22k</text>
<text x="180" y="276.3">ESDA6V1-5SC6</text>
<text x="197.7" y="276.3">ESDA6V1-5SC6</text>
<text x="270.7" y="276.1">H2</text>
<text x="271.1" y="278.6">MountingHole</text>
</g>
<g font-size="1.8" fill="#848400">
<text x="206.5" y="34">File: fm-rpt-control-roger-beep.kicad_sch</text>
<text x="250.6" y="34.1">File: fm-rpt-control-audio-filters.kicad_sch</text>
<text x="296.1" y="34.7">File: fm-rpt-control-555.kicad_sch</text>
<text x="53.4" y="37.8">File: fm-rpt-control-power.kicad_sch</text>
<text x="92.2" y="37.8">File: fm-rpt-connectors.kicad_sch</text>
</g>
<g font-size="1.8">
<text x="177.8" y="41.6">~{DBC_CNTRL}</text>
<text x="177.8" y="36.5">DBC_CNTRL</text>
<text x="344.2" y="39.1">CNTR1</text>
<text x="370.8" y="39.1">CNTR2</text>
<text x="344.2" y="46.7">CNTR0</text>
<text x="370.8" y="46.7">CNTR3</text>
<text x="151.1" y="53">CLK 3</text>
<text x="168.4" y="50.6">5 DPX_RETRN_DBC 4</text>
<text x="175.3" y="55.6">DBC_CNTRL 5</text>
<text x="308.6" y="55.6">CLK</text>
<text x="340.4" y="58.1">CNTR1</text>
<text x="340.4" y="55.6">CNTR0</text>
<text x="145.7" y="62.3" transform="rotate(-90 145.7 62.3)">RETRANSMIT</text>
<text x="317" y="63.3">2</text>
<text x="320.5" y="64.2">CLR</text>
<text x="340.4" y="60.6">CNTR2</text>
<text x="340.4" y="63.2">CNTR3</text>
<text x="231.1" y="67">CLK 12</text>
<text x="153.7" y="72.1">~{DBC_CNTRL}</text>
<text x="218.4" y="73.3">DPX_TX_TAIL_CLR 13</text>
<text x="331.5" y="72.1">TAIL0</text>
<text x="331.5" y="74.6">TAIL1</text>
<text x="331.5" y="77.2">TAIL2</text>
<text x="171.4" y="78.4">RETRANSMIT_NEVER_DBCED</text>
<text x="224.8" y="83.5">~{DPX_INHIBIT}</text>
<text x="224.8" y="81">RETRANSMIT_NEVER_DBCED</text>
<text x="276.9" y="83.5">~{DPX_INHIBIT}</text>
<text x="331.5" y="79.7">TAIL3</text>
<text x="379.7" y="81">DPX_TX_TAIL_CLR</text>
<text x="170.9" y="84.8">~{DPX_INHIBIT_FROM_RMT} 12</text>
<text x="276.9" y="86">~{DPX_LOOP_INHIBIT}</text>
<text x="225.3" y="94.9">RETRANSMIT_DBCED</text>
<text x="348" y="91.1">RETRANSMIT_NEVER_DBCED 3</text>
<text x="354.3" y="93.7">RETRANSMIT_DBCED 5</text>
<text x="224.8" y="97.5">RETRANSMIT_NEVER_DBCED</text>
<text x="224.8" y="100">ROGER_PTT_SW</text>
<text x="275.6" y="100">DPX_PTT_CNTRL_WO_ROGER</text>
<text x="349.2" y="106.4">DUPLEX_PTT_ISOL</text>
<text x="185.4" y="111.4">RETRANSMIT_DBCED10</text>
<text x="189.2" y="114">SPX_MSTR_ENABLE</text>
<text x="289.6" y="114">DPX_PTT_CNTRL_AFT_INIBIT</text>
<text x="293.7" y="108.9">DPX_PTT_CNTRL</text>
<text x="349.2" y="111.4">SIMPLEX_PTT_ISOL</text>
<text x="236.2" y="119.1">SPX_PTT_CNTRL</text>
<text x="148.2" y="123.2" transform="rotate(-90 148.2 123.2)">~{RETRANSMIT_NEVER_DBCED}</text>
<text x="150.8" y="123.2" transform="rotate(-90 150.8 123.2)">~{DPX_INHIBIT_FROM_RMT}</text>
<text x="153.3" y="123.2" transform="rotate(-90 153.3 123.2)">RETRANSMIT_FROM_ACC</text>
<text x="236.2" y="131.8">~{SPX_INHIBIT}10</text>
<text x="182.9" y="136.8">SPX_CTCSS_DET_ISOL</text>
<text x="99.1" y="139.4">SPX_CTCSS_DET_ISOL</text>
<text x="233" y="138.8">SPX_PTT_AFT_INHIBIT</text>
<text x="293.4" y="141.9">DUPLEX_PTT_ISOL</text>
<text x="200" y="144.5">SPX_INHIBIT_CNTRL</text>
<text x="274" y="148.6" transform="rotate(-90 274 148.6)">DPX_PTT_DIR_FROM_RMT</text>
<text x="118.1" y="153.4">~{DPX_INHIBIT_FROM_RMT}</text>
<text x="155.9" y="155" transform="rotate(-90 155.9 155)">~{SPX_INHIBIT_FROM_RMT}</text>
<text x="185.4" y="150.8">~{SPX_PTT_DIR_FROM_RMT}</text>
<text x="252.4" y="150.9">11 SIMPLEX_PTT_ISOL</text>
<text x="118.1" y="158.4">~{SPX_INHIBIT_FROM_RMT}</text>
<text x="185.4" y="157.2">SPX_PTT_FROM_ACC</text>
<text x="227.3" y="158.4">~{DPX_PTT_DIR_FROM_RMT}13</text>
<text x="118.1" y="163.5">~{SPX_PTT_DIR_FROM_RMT}</text>
<text x="227.3" y="167.3">~{DPX_LOOP_INHIBIT}</text>
<text x="118.1" y="168.6">~{DPX_PTT_DIR_FROM_RMT}</text>
<text x="118.1" y="171.1">~{DPX_LOOP_INH_FROM_RMT}</text>
<text x="185.4" y="169.9">DPX_LOOP_INH_FROM_ACC</text>
<text x="185.4" y="172.4">DPX_PTT_FROM_ACC</text>
<text x="276.5" y="171.5" transform="rotate(-90 276.5 171.5)">DPX_PTT_FROM_ACC</text>
<text x="185.4" y="174.9">SPX_ENABLE_CNTRL</text>
<text x="185.4" y="177.5">SPX_MSTR_ENABLE</text>
<text x="248.9" y="181.3">~{SPX_INHIBIT}1</text>
<text x="242.6" y="186.4">SPX_MSTR_ENABLE</text>
<text x="17.8" y="205.4">~{DPX_INHIBIT}</text>
<text x="274.3" y="209.2">OACC_DPX_RETRN_ND</text>
<text x="17.8" y="213">~{SPX_INHIBIT}</text>
<text x="166" y="213.4" transform="rotate(-90 166 213.4)">DPX_LOOP_INH_FROM_ACC</text>
<text x="168.6" y="213.4" transform="rotate(-90 168.6 213.4)">RETRANSMIT_FROM_ACC</text>
<text x="171.1" y="213.4" transform="rotate(-90 171.1 213.4)">SPX_INHIBIT_FROM_ACC</text>
<text x="173.6" y="213.4" transform="rotate(-90 173.6 213.4)">SPX_PTT_FROM_ACC</text>
<text x="176.2" y="213.4" transform="rotate(-90 176.2 213.4)">DPX_PTT_FROM_ACC</text>
<text x="178.7" y="213.4" transform="rotate(-90 178.7 213.4)">SPX_ENABLE_FROM_ACC</text>
<text x="181.3" y="213.4" transform="rotate(-90 181.3 213.4)">DPX_INHIBIT_FROM_ACC</text>
<text x="274.3" y="211.8">OACC_DPX_PTT</text>
<text x="274.3" y="214.3">OACC_SPX_PTT</text>
<text x="15.2" y="220.7">ROGER_PTT_SW</text>
<text x="274.3" y="216.9">OACC_SPX_ENABLE</text>
<text x="274.3" y="219.4">OACC_DPX_RETRN</text>
<text x="336.5" y="221.9">RETRANSMIT_NEVER_DBCED</text>
<text x="12.1" y="227.7">SPX_MSTR_ENABLE</text>
<text x="221" y="225.7">IACC_DPX_INHIBIT</text>
<text x="276.9" y="227">~{DPX_MUTE}</text>
<text x="284.4" y="225.5">74AHC04</text>
<text x="336.5" y="227">SIMPLEX_PTT_ISOL</text>
<text x="336.5" y="224.5">DUPLEX_PTT_ISOL</text>
<text x="163.2" y="228.3">RETRNSMIT_ND_FROM_ACC</text>
<text x="181" y="230.8">2Y3</text>
<text x="221" y="228.3">IACC_SPX_ENABLE</text>
<text x="221" y="230.8">IACC_DPX_PTT</text>
<text x="336.5" y="229.6">SPX_ENABLE_CNTRL</text>
<text x="336.5" y="232.1">RETRANSMIT_DBCED</text>
<text x="19" y="234.6">CNTR_CLR</text>
<text x="262.5" y="241.1">17 ACC_+V</text>
<text x="262.5" y="243.6">19 ACC_5V</text>
<text x="224.8" y="246.1">IACC_DPX_LOOP_INHIBIT</text>
<text x="262.5" y="246.2">21 IACC_DPX_MUTE</text>
<text x="186.3" y="256.9" transform="rotate(-90 186.3 256.9)">DPX_LOOP_INH_CNTRL</text>
</g>
<g font-size="1.8" fill="#008400">
<text x="214.8" y="60.7">3RETRANSMIT_DBCED 1</text>
<text x="262.9" y="60.6">DPX_TX_TAIL</text>
<text x="312.4" y="63.2">CNTR_CLR</text>
<text x="153.3" y="155" transform="rotate(-90 153.3 155)">SPX_ENABLE_CNTRL</text>
<text x="358.5" y="155.6">U15C</text>
<text x="221" y="218.1">IACC_OE</text>
<text x="221" y="233.4">IACC_SPX_PTT</text>
<text x="221" y="235.9">IACC_SPX_INHIBIT</text>
<text x="224.8" y="241">IACC_RETRNSMT</text>
<text x="224.8" y="243.5">IACC_RETRNSMT_ND</text>
</g>
<g font-size="1.4" fill="#840000">
<text x="120.9" y="139.5">1</text>
<text x="120.9" y="142">2</text>
<text x="131.1" y="140.8">4</text>
<text x="134.9" y="140.8">2</text>
<text x="145" y="140.8">4</text>
<text x="84.3" y="153.5">20</text>
<text x="114.8" y="153.5">18</text>
<text x="115.2" y="156">3</text>
<text x="84.3" y="161.1">19</text>
<text x="84.7" y="158.5">1</text>
<text x="114.8" y="158.5">16</text>
<text x="115.2" y="161.1">5</text>
<text x="84.7" y="166.2">2</text>
<text x="114.8" y="163.6">14</text>
<text x="115.2" y="166.2">7</text>
<text x="84.3" y="173.8">15</text>
<text x="84.3" y="168.7">17</text>
<text x="84.7" y="171.2">4</text>
<text x="114.8" y="168.7">12</text>
<text x="115.2" y="171.2">9</text>
<text x="84.3" y="178.9">13</text>
<text x="84.7" y="176.3">6</text>
<text x="84.3" y="183.9">11</text>
<text x="84.7" y="181.4">8</text>
<text x="84.3" y="189">10</text>
<text x="302.7" y="209.3">18</text>
<text x="333.2" y="209.3">20</text>
<text x="187.2" y="213.1">18</text>
<text x="187.6" y="215.7">3</text>
<text x="217.7" y="213.1">20</text>
<text x="302.7" y="214.4">16</text>
<text x="303.1" y="211.9">3</text>
<text x="333.6" y="214.4">1</text>
<text x="187.2" y="218.2">16</text>
<text x="187.6" y="220.8">5</text>
<text x="217.7" y="220.8">19</text>
<text x="218" y="218.2">1</text>
<text x="302.7" y="219.5">14</text>
<text x="303.1" y="217">5</text>
<text x="333.2" y="217">19</text>
<text x="187.2" y="223.3">14</text>
<text x="187.6" y="225.8">7</text>
<text x="218" y="225.8">2</text>
<text x="302.7" y="224.6">12</text>
<text x="303.1" y="222">7</text>
<text x="303.1" y="227.1">9</text>
<text x="333.2" y="224.6">17</text>
<text x="333.6" y="222">2</text>
<text x="333.6" y="227.1">4</text>
<text x="150.7" y="228.4">4</text>
<text x="160.9" y="228.4">2</text>
<text x="168.5" y="232.2">4</text>
<text x="178.7" y="233.5">1</text>
<text x="178.7" y="230.9">2</text>
<text x="187.2" y="228.4">12</text>
<text x="187.6" y="230.9">9</text>
<text x="217.7" y="233.5">15</text>
<text x="217.7" y="228.4">17</text>
<text x="218" y="230.9">4</text>
<text x="333.2" y="229.7">15</text>
<text x="333.6" y="232.2">6</text>
<text x="217.7" y="238.5">13</text>
<text x="218" y="236">6</text>
<text x="333.2" y="239.8">11</text>
<text x="333.2" y="234.7">13</text>
<text x="333.6" y="237.3">8</text>
<text x="217.7" y="243.6">11</text>
<text x="218" y="241.1">8</text>
<text x="333.2" y="244.9">10</text>
<text x="217.7" y="248.7">10</text>
<text x="125.3" y="267.8">2</text>
<text x="135.5" y="267.8">4</text>
</g>
<g font-size="1.4" fill="#008484">
<text x="88.6" y="154.2">VCC</text>
<text x="109.5" y="154.2">1Y0</text>
<text x="88.6" y="159.3">~1OE</text>
<text x="88.6" y="161.8">~2OE</text>
<text x="109.5" y="159.3">1Y1</text>
<text x="109.5" y="156.8">2Y0</text>
<text x="109.5" y="161.8">2Y1</text>
<text x="88.6" y="166.9">1A0</text>
<text x="109.5" y="164.4">1Y2</text>
<text x="109.5" y="166.9">2Y2</text>
<text x="88.6" y="169.5">2A0</text>
<text x="88.6" y="172">1A1</text>
<text x="109.5" y="169.5">1Y3</text>
<text x="109.5" y="172">2Y3</text>
<text x="88.6" y="179.6">2A2</text>
<text x="88.6" y="174.5">2A1</text>
<text x="88.6" y="177.1">1A2</text>
<text x="88.6" y="184.7">2A3</text>
<text x="88.6" y="182.2">1A3</text>
<text x="88.6" y="189.8">GND</text>
<text x="191.5" y="213.9">1Y0</text>
<text x="211.9" y="213.9">VCC</text>
<text x="307.1" y="215.2">1Y1</text>
<text x="307.1" y="210.1">1Y0</text>
<text x="307.1" y="212.6">2Y0</text>
<text x="327.5" y="210.1">VCC</text>
<text x="327.6" y="215.2">~1OE</text>
<text x="191.5" y="219">1Y1</text>
<text x="191.5" y="216.4">2Y0</text>
<text x="191.5" y="221.5">2Y1</text>
<text x="212.1" y="219">~1OE</text>
<text x="212.1" y="221.5">~2OE</text>
<text x="307.1" y="220.3">1Y2</text>
<text x="307.1" y="217.7">2Y1</text>
<text x="327.6" y="217.7">~2OE</text>
<text x="191.5" y="224.1">1Y2</text>
<text x="191.5" y="226.6">2Y2</text>
<text x="212.3" y="226.6">1A0</text>
<text x="307.1" y="225.3">1Y3</text>
<text x="307.1" y="222.8">2Y2</text>
<text x="307.1" y="227.9">2Y3</text>
<text x="327.9" y="225.3">2A0</text>
<text x="327.9" y="222.8">1A0</text>
<text x="327.9" y="227.9">1A1</text>
<text x="191.5" y="229.1">1Y3</text>
<text x="191.5" y="231.7">2Y3</text>
<text x="212.3" y="229.1">2A0</text>
<text x="212.3" y="231.7">1A1</text>
<text x="327.9" y="230.4">2A1</text>
<text x="327.9" y="233">1A2</text>
<text x="212.3" y="239.3">2A2</text>
<text x="212.3" y="234.2">2A1</text>
<text x="212.3" y="236.8">1A2</text>
<text x="327.9" y="235.5">2A2</text>
<text x="327.9" y="238">1A3</text>
<text x="212.3" y="244.4">2A3</text>
<text x="212.3" y="241.8">1A3</text>
<text x="327.3" y="245.7">GND</text>
<text x="327.9" y="240.6">2A3</text>
<text x="211.7" y="249.5">GND</text>
</g>
<g font-size="1.1" fill="#840000">
<text x="380" y="92.6">R</text>
<text x="385" y="95.1">G</text>
<text x="380" y="97.7">B</text>
</g>
</g></defs>
<g fill="none" stroke="#840000" stroke-width=".18">
<path d="M10 10h400v277h-400zM12 12h396v273h-396zM60 10v2M110 10v2M160 10v2M210 10v2M260 10v2M310 10v2M360 10v2M377.2 17.8l-.8 1.3M377.2 17.8v2.6M377.2 17.8l.8 1.3"/>
<path d="M388.6 17.8l-.7 1.3M388.6 17.8v2.6M388.6 17.8l.8 1.3M398.8 14.1h2.5v5.1l-1.3 1.2-1.2-1.2zM399.4 15.1l1.3 .4-1.3 .4M161.3 31.9h2.5v5.1l-1.2 1.1-1.3-1.1zM162 32.9l1.2 .4-1.2 .4M166.4 39.4h2.5M173.1 37.1l-3.2 2.1M174 36.9h2.5M189.2 36.9h1.3M195.6 36.9h1.2"/>
<path d="M198.1 36.9h2.6M200.7 35v3.8M325.8 37.5v3.8M325.8 39.4h3.8M334.6 39.4h8.9M339.1 21.6v2.8M339.1 26.5v2.7M348 21.6v2.8M348 26.5v2.7M352.4 39.4h3.8M352.4 37.5v3.8M356.9 21.6v2.8"/>
<path d="M356.9 26.5v2.7M361.3 39.4h8.9M367 21.6v2.8M367 26.5v2.7M377.2 21.6v2.8M377.2 26.5v2.7M383.5 38.2h2.6v5.2l-1.3 1.1-1.3-1.1zM384.2 39.2l1.3 .5-1.3 .4M388.6 21.6v2.8M388.6 26.5v2.7M396.2 38.2h2.6v5.2l-1.3 1.1-1.3-1.1zM396.9 39.2l1.3 .5-1.3 .4"/>
<path d="M398.1 33.7h3.9M400 21.6v2.8M400 26.5v2.7M400 31.2v2.5M29.8 52.7v3.9M45.7 52.7v3.9M61 52.7v3.9M76.2 52.7v3.9M154.9 50.8h2.6M154.9 53.4h2.6M157.5 52.7l1.2 .7-1.2 .6M162.6 45.8v2.5"/>
<path d="M162.6 58.5v2.5M167.6 55.9h2.6M167.6 50.8h2.6M174 41.9h2.5M185.4 55.9h3.8M185.4 50.8h3.8M195.6 41.9h1.2M196.8 53.4h3.9M198.1 41.9h2.6M200.7 40v3.9M201.9 58.5h4.3M208.9 57.2h-3.2a6.6 6.6 0 0 1 0 7.6h3.2"/>
<path d="M220.2 50.8h19.8v2.6h-19.8l-1.1-1.3zM288.9 59.7h-3.2a6.6 6.6 0 0 1 0 7.6h3.2M315 55.9h5M325.8 47h3.8M325.8 45.1v3.8M334.6 47h8.9M335.3 55.9h5.1M335.3 58.5h5.1M336.7 40.2l-1.5 1.5h.7h-.7v-.8M336.7 47.8l-1.5 1.5h.7h-.7v-.7M337.9 40.2l-1.5 1.5h.8h-.8v-.8M337.9 47.8l-1.5 1.5h.8h-.8v-.7"/>
<path d="M348 55.9h5.1M348 58.5h5.1M352.4 47h3.8M352.4 45.1v3.8M363.3 40.2l-1.5 1.5h.8h-.8v-.8M364.6 40.2l-1.5 1.5h.8h-.8v-.8M365.1 47h5.1M384.8 45.8v5M397.5 45.8v5M10 60h2M29.8 65.4v2.6M45.7 65.4v2.6"/>
<path d="M61 65.4v2.6M76.2 65.4v2.6M128.3 67.3v2.6M128.3 72.4v1.3M128.3 78.8v1.2M128.3 67.3l-.8 1.3M128.3 67.3l.7 1.3M129.8 62.3h12.6l1.1 1.2-1.1 1.3h-12.6zM132.1 72.4h2.5l1.9 1.9M137.2 74.3v7M142.2 72.4h-2.5l-1.9 1.9M148.6 78.8h3.8"/>
<path d="M153.1 61.6h5.2l1.1 1.3-1.1 1.3h-5.2zM161.3 78.8h2.5M163.8 67.3h3.8M163.8 72.4h3.8M175.3 69.9h3.8M184.1 75h4.4M184.1 69.9h4.4M191.1 68.6h-3.1a6.6 6.6 0 0 1 0 7.6h3.1M195.6 72.4h3.8M201.9 63.5h4.3M213.4 61h3.8M225.4 68.6h3.8"/>
<path d="M227.3 68.6v2.6M233.7 61h5.1M233.7 67.3h5.1M233.7 73.7h5.1M233.7 71.2h5.1M254 61h5.1M254 73.7h5.1M266.7 67.3h4.3M266.7 72.4h4.3M269.7 76.9h26.7v2.5h-26.7l-1.1-1.3zM273.7 66.1h-3.2a6.6 6.6 0 0 1 0 7.6h3.2M278.1 69.9h3.8"/>
<path d="M281.9 61h4.5M281.9 66.1h4.5M283.1 71.2h18v2.5h-18l-1.2-1.3zM293.4 63.5h7.6M302.3 69.3l-.8 1.2M302.3 69.3v2.5M302.3 69.3l.7 1.2M304.8 72.4h1.3M309.9 63.5h2.5M311.1 75h1.3M311.1 72.4h1.3M315 63.5h5"/>
<path d="M317.5 77.5h1.3M317.5 75h1.3M323.8 77.5h1.3M335.3 63.5h5.1M335.3 61h5.1M343.5 76.2h3.8M345.4 76.2v2.6M348 63.5h5.1M348 61h5.1M348 73.7h5.1M348 71.2h5.1M348 66.1h5.1"/>
<path d="M348 78.8h5.1M348 68.6h5.1M373.4 78.8h5.1M382.9 75h3.8M384.8 66.1v5.1M384.8 72.4v2.6M395.6 75h3.8M397.5 66.1v5.1M397.5 72.4v2.6M408 60h2M137.2 86.4v3.8l1.9 1.9M139.1 93.4l-1.9 1.9v5.1"/>
<path d="M139.1 92.7h5.7M153.7 92.7v1.3M153.7 99.1v1.3M172.7 90.2h3.8M185.4 90.2h2.6M192.4 99.1h-3.2a6.6 6.6 0 0 1 0 7.6h3.2M194.3 90.2h4.3M194.3 85.1h4.3M201.3 83.9h-3.2a6.6 6.6 0 0 1 0 7.6h3.2M205.7 87.7h3.8M262.9 90.2h2.5M262.9 95.3h2.5"/>
<path d="M266.3 90.5l3.2 2M270.5 92.7h2.5M275.6 90.2h3.8M275.6 95.3h3.8M287 92.7h8.1M290.8 97.8h4.3M297.8 91.5h-3.2a6.6 6.6 0 0 1 0 7.6h3.2M302.3 95.3h3.8M311 82.6h12.7v2.5h-12.7l-1.1-1.2zM323.8 80h1.3M330.2 80h1.3M332.6 87.4l-1 3.9"/>
<path d="M332.7 81.3v5.1M332.7 91.5v5.1M335.2 87.4l-1.1 3.9M335.3 81.3v5.1M335.3 91.5v5.1M337.7 87.4l-1 3.9M337.8 81.3v5.1M337.8 91.5v5.1M338.5 99.1h3.8M340.2 87.4l-1 3.9M340.4 81.3v5.1M340.4 91.5v7.6"/>
<path d="M342.9 81.3h2.5M342.9 81.3l1.3 .8M344.2 80.6l-1.3 .7M344.8 86.4h3.8M346.7 83.9v2.5M348 81.3h5.1M348 83.9h5.1M366.2 95.3h4.8l1.1 1.3-1.1 1.2h-4.8zM373.4 96.6h15.2M373.4 81.3h5.1M373.4 83.9h5.1M373.4 94h15.2"/>
<path d="M373.4 91.5h16.5M378.5 89.4l.7-.2-.2 .8M378.5 94.5l.7-.2-.2 .7M379.2 94.3l-1 1M379.2 89.2l-1 1M379.5 94.5l.7-.2-.2 .7M379.5 89.4l.7-.2-.2 .8M380.2 94.3l-1 1M380.2 89.2l-1 1M383.5 92l.8-.3-.3 .8M384.3 91.7l-1 1M384.6 92l.7-.3-.2 .8"/>
<path d="M385.3 91.7l-1 1M389.9 94h1.3M392.4 96.6h1.3M398.8 96.6h1.2M400 91.5h2.6M402.6 89.6v3.8M10 110h2M135.3 100.4h3.8M185.4 100.4h4.3M185.4 105.4h4.3M196.8 102.9h3.9M203.2 106.7h4.3"/>
<path d="M203.2 111.8h4.3M205.1 119.4h-3.2a6.6 6.6 0 0 1 0 7.6h3.2M210.2 105.4h-3.2a6.6 6.6 0 0 1 0 7.7h3.2M214.6 109.3h3.8M221 116.9h3.8M227.2 108h23.1l1.2 1.3-1.2 1.2h-23.1zM232.4 119.4h3.8M246.4 114.3h2.5M246.4 112.4v3.8M250.2 114.3h1.3M256.5 114.3h1.3M259.1 109.3h2.5"/>
<path d="M259.1 114.3h2.5M262.5 109.5l3.2 2M266.7 111.8h2.5M278.1 106.7h4.3M278.1 111.8h4.3M285.1 119.4h-3.2a6.6 6.6 0 0 1 0 7.6h3.2M285.1 105.4h-3.2a6.6 6.6 0 0 1 0 7.7h3.2M289.6 109.3h3.8M308.6 104.2h3.8M308.6 109.3h3.8M320 106.7h3.8M367 106.7h15.3"/>
<path d="M367 111.8h15.3M378.2 103.4v-.7h-.8h.8l-1.5 1.5M379.5 104.4v-.7h-.8h.8l-1.5 1.5M382.3 113.2h2.5v5.1l-1.3 1.1-1.2-1.1zM382.9 114.2l1.3 .4-1.3 .4M386.1 106.7h1.2M386.1 111.8h1.2M392.4 106.7h3.8M392.4 111.8h3.8M396.2 104.8v3.8M396.2 109.9v3.8M408 110h2"/>
<path d="M76.6 138.5h21.3l1.2 1.2-1.2 1.3h-21.3zM117.5 129.6h19.8l1.1 1.2-1.1 1.3h-19.8zM119.4 139.7h3.8M182.9 120.7h3.8M195.6 120.7h6.8M198.1 125.8h4.3M202.6 137.2h4.3M202.6 132.1h4.3M209.5 130.8h-3.1a6.6 6.6 0 0 1 0 7.7h3.1M210.8 123.2h2.6M215.3 134.7h2.5M221 134.7h3.8"/>
<path d="M221 122h3.8M221 129.6h3.8M232.4 132.1h3.8M248.3 132.1h3.8M248.3 127h3.8M259.7 129.6h3.8M278.1 125.8h4.3M278.1 120.7h4.3M278.1 134.7h4.3M278.1 139.7h4.3M285.1 133.4h-3.2a6.6 6.6 0 0 1 0 7.6h3.2M289.6 123.2h3.8"/>
<path d="M289.6 137.2h3.8M295.4 132.8h5.1l1.1 1.2-1.1 1.3h-5.1zM304.2 134h2.5M306.7 132.8h5.1M309.2 131v1.8M311.8 134h2.5M383.5 120.7v5.1M77.5 158.8h2.5M77.5 156.9v3.8M78.7 144.9h2.6v5.2l-1.3 1.1-1.3-1.1zM79.4 145.9l1.3 .4-1.3 .5M82.5 158.8h5.1"/>
<path d="M82.5 153.7h5.1M113 158.8h5.1M113 153.7h5.1M113 156.2h5.1M119.4 142.3h3.8M129.5 141h7.7M138.4 141l.7-.6 .6 .6-.6 .6zM138.4 141.6h1.3M144.8 141h2.5M184.1 147.4h2.6M184.1 147.4l1.3 .7M185.4 146.6l-1.3 .8"/>
<path d="M186.7 142.3h5.1M186.7 140.4v3.8M189.2 147.4h2.6M195.8 145.1l-3.1 2M196.8 144.8h2.6M208.3 151.2h3.8M221 151.2h6.8M223.5 146.1h4.3M230.5 144.8h-3.2a6.6 6.6 0 0 1 0 7.6h3.2M234.9 148.6h3.9M240 148.6h4.3M240 153.7h4.3"/>
<path d="M247 147.4h-3.2a6.6 6.6 0 0 1 0 7.6h3.2M251.5 158.8h3.8M251.5 151.2h3.8M264.2 158.8h2.5M315 142.3h8.8M322.8 146.3h4.6v.5h-4.6zM323.2 155h3.8M323.3 145.1h1.1M323.8 144.6v1M325.1 143.5v2.8M325.1 148.4v2.8M325.1 152.4v2.6"/>
<path d="M330 141h26v2.5h-26l-1.1-1.2zM344.2 153.7v5.1M372.1 153.7v5.1M381.6 149.9h3.8M383.5 141v5.1M383.5 147.4v2.5M386.1 153.7v5.1M398.8 147.5h2.5v5.1l-1.3 1.1-1.2-1.1zM399.4 148.5l1.3 .4-1.3 .4M400 153.7v5.1M10 160h2M49.1 175.3h22.2l1.1 1.3-1.1 1.2h-22.2z"/>
<path d="M53.9 165.1h17.4l1.1 1.3-1.1 1.3h-17.4zM54 170.2h17.3l1.1 1.3-1.1 1.3h-17.3zM82.5 176.6h5.1M82.5 168.9h5.1M82.5 179.1h5.1M82.5 174h5.1M82.5 161.3h5.1M82.5 166.4h5.1M82.5 171.5h5.1M113 168.9h5.1M113 163.9h5.1M113 161.3h5.1"/>
<path d="M113 166.4h5.1M113 171.5h5.1M133.3 179.2h2.6v5.1l-1.3 1.2-1.3-1.2zM191.8 165.1h3.8M204.5 165.1h2.5M210.8 165.1h4.3M210.8 170.2h4.3M217.8 163.9h-3.2a6.6 6.6 0 0 1 0 7.6h3.2M223.5 167.7h2.6M246.2 166.4h18.6v2.5h-18.6l-1.1-1.2zM278.7 162.6h14.2l1.1 1.3-1.1 1.2h-14.2zM295.3 163.9h2.5"/>
<path d="M297.2 176.6h1.2M301 179.7v3.9M302 161.6l-3.2 2M302.9 161.3h2.5M302.9 166.4h2.5M303.5 176.6h6.4v3.8v-1.9M307.8 160.1h17.8v2.5h-17.8l-1.1-1.3zM309.9 179.7v1.9h-5.1M311.9 179.6h1.3l-.4 .1v-.2l.4 .1M311.9 178.6h1.3l-.4 .1v-.2l.4 .1M320 176.6h-3.1l-1.9 1.9M323.1 175.3h10.3v2.5h-10.3l-1.2-1.2z"/>
<path d="M344.2 174v7.6M358.1 174v2.6M372.1 174v5.1M386.1 174v5.1M400 174v5.1M401.3 179.2h2.6v5.1l-1.3 1.2-1.3-1.2zM408 160h2M48 185.5h23.3l1.1 1.2-1.1 1.3h-23.3zM49.8 180.4h21.5l1.1 1.2-1.1 1.3h-21.5zM77.5 189.3h2.5M77.5 187.4v3.8M82.5 181.6h5.1"/>
<path d="M82.5 184.2h5.1M82.5 189.3h5.1M134 180.2l1.3 .4-1.3 .4M139.7 188h1.3M146 188h1.3M183.5 186.7l1.3 .8M188 186.7h2.5M188 191.8h2.5M189.2 198.2h2.6M189.2 196.3v3.8M193 198.2h1.3M194.6 189.5l-3.2 2.1"/>
<path d="M195.6 189.3h2.5M199.4 198.2h1.3M200.7 184.2h3.8M200.7 189.3h3.8M210.7 190.5h13l1.1 1.3-1.1 1.3h-13zM212.1 186.7h3.8M226.1 186.7h3.8M226.1 191.8h3.8M237.5 189.3h3.8M260.3 181.6h3.9M260.3 186.7h3.9M271.8 184.2h3.8"/>
<path d="M297.2 190.5h1.2M301 181.6h2.5M301 195.6h2.5M301 193.7v3.8M303.5 190.5h6.4v3.8v-1.9M309.9 193.7v1.9h-5.1M311.9 193.6h1.3l-.4 .1v-.2l.4 .1M311.9 192.6h1.3l-.4 .1v-.3l.4 .2M316.9 181.6h3.1M316.9 195.6h3.1M320 190.5h-3.1l-1.9 1.9M321.3 195.6h1.3v-1.3l1.2 1.3-1.2 1.3v-1.3"/>
<path d="M322.6 181.6h1.2v-1.2l1.3 1.2-1.3 1.3v-1.3M323.7 189.3h10.3v2.5h-10.3l-1.1-1.3zM342.3 181.6h3.8M358.1 185.5v5M372.1 185.5v5M386.1 185.5v5M400 185.5v5M402 180.2l1.3 .4-1.3 .4M10 210h2M29.2 213.4h8.9M29.2 205.8h8.9M36.3 204.3v-.8h-.7h.7l-1.5 1.5"/>
<path d="M36.3 219.5v-.8h-.7h.7l-1.5 1.6M36.3 211.9v-.8h-.7h.7l-1.5 1.5M37.6 204.3v-.8h-.8h.8l-1.5 1.5M37.6 219.5v-.8h-.8h.8l-1.5 1.6M37.6 211.9v-.8h-.8h.8l-1.5 1.5M43.2 213.4h1.2M43.2 205.8h1.2M185.4 218.5h5.1M185.4 213.4h5.1M185.4 215.9h5.1M215.9 218.5h5.1M215.9 213.4h5.1"/>
<path d="M228.6 218.5h2.5M231.1 216.6v3.8M236.7 219.7h14.9l1.1 1.3-1.1 1.3h-14.9zM293.4 214.7h1.2M293.4 212.1h1.2M293.4 219.7h1.2M293.4 217.2h1.2M299.7 209.6h6.4M299.7 214.7h6.4M299.7 212.1h6.4M299.7 219.7h6.4M299.7 217.2h6.4"/>
<path d="M331.5 209.6h5M331.5 214.7h5M331.5 217.2h5M339.6 208.3h5.1v2.6h-5.1l-1.1-1.3zM342.3 214.7h2.5M342.9 209l.4 1.3 .4-1.3M344.8 212.8v3.8M358.1 205.8v5.1M372.1 205.8v5.1M379.1 213.4h3.8M381 210.9v2.5M386.1 205.8v5.1"/>
<path d="M395.6 214.8h2.5v5.1l-1.2 1.1-1.3-1.1zM396.3 215.8l1.2 .4-1.2 .4M400 205.8v5.1M408 210h2M29.2 221h8.9M29.2 235h8.9M29.2 228h8.9M36.3 233.5v-.8h-.7h.7l-1.5 1.5M36.3 226.5v-.8h-.7h.7l-1.5 1.5M37.6 233.5v-.8h-.8h.8l-1.5 1.5M37.6 226.5v-.8h-.8h.8l-1.5 1.5M43.2 221h1.2"/>
<path d="M43.2 235h1.2M43.2 228h1.2M48.3 238.2v2.5M144.8 227.3h2.5v18l-1.3 1.1-1.2-1.1zM149.2 228.6h2.6M156.8 229.3h1.3M157.5 228l.6 .6-.6 .7-.7-.7zM159.4 228.6h3.8M167 232.4h3.8M176.5 231.2h4.5M176.5 233.7h4.5M185.4 221h5.1"/>
<path d="M185.4 231.2h5.1M185.4 223.6h5.1M185.4 226.1h5.1M185.4 228.6h5.1M215.9 221h5.1M215.9 231.2h5.1M215.9 233.7h5.1M215.9 236.3h5.1M215.9 238.8h5.1M215.9 226.1h5.1M215.9 228.6h5.1M236.7 222.3h14.9l1.1 1.3-1.1 1.2h-14.9z"/>
<path d="M247.6 238.8h2.6M247.6 236.9v3.8M252.7 221h3.8M252.7 231.2h3.8M252.7 233.7h3.8M252.7 236.3h3.8M252.7 238.8h3.8M252.7 223.6h3.8M252.7 226.1h3.8M252.7 228.6h3.8M256.5 238.7h1.3v.2h-1.3zM256.5 236.1h1.3v.3h-1.3z"/>
<path d="M256.5 233.6h1.3v.2h-1.3zM256.5 231h1.3v.3h-1.3zM256.5 228.5h1.3v.3h-1.3zM256.5 226h1.3v.2h-1.3zM256.5 223.4h1.3v.3h-1.3zM256.5 220.9h1.3v.2h-1.3zM260.3 238.7h1.3v.2h-1.3zM260.3 236.1h1.3v.3h-1.3zM260.3 233.6h1.3v.2h-1.3zM260.3 231h1.3v.3h-1.3zM260.3 228.5h1.3v.3h-1.3zM260.3 226h1.3v.2h-1.3z"/>
<path d="M260.3 223.4h1.3v.3h-1.3zM260.3 220.9h1.3v.2h-1.3zM261.6 221h3.8M261.6 231.2h3.8M261.6 233.7h3.8M261.6 236.3h3.8M261.6 238.8h5.1M261.6 223.6h3.8M261.6 226.1h3.8M261.6 228.6h3.8M266.7 236.9v3.8M278.8 239.8h-1.1l-3 3.1h-1"/>
<path d="M280.5 229.9h10.9v2.5h-10.9l-1.1-1.2zM294.6 239.4v1.3M297.2 227.4h8.9M301 224.8h5.1M301 222.3h5.1M331.5 235h5M331.5 232.4h5M331.5 237.5h5M331.5 224.8h5M331.5 229.9h5M331.5 222.3h5M331.5 227.4h5"/>
<path d="M337.8 237.5h2.6M340.4 235.6v3.8M365.8 222.3v5.1M365.8 238.8v5.1M375.9 222.3v5.1M375.9 232.4v5.1M386.1 222.3v5.1M386.1 232.4v5.1M396.9 222.3v5.1M46.4 240.7h3.8M86.3 254h25l1.1 1.3-1.1 1.3h-25zM113.7 255.3h2.5"/>
<path d="M121.9 251.5h3.2a6.7 6.7 0 0 0 0 7.6h-3.2M124.6 257.8h4.3M124.6 252.8h6.8M140.3 252.8h3.8M154.4 254h5.1l1.2 1.3-1.2 1.3h-5.1zM160 258.5v3.8M164.5 255.3h2.5M171.1 258.1l-3.2 2M172.1 257.8h2.5M215.9 243.9h5.1M215.9 241.3h5.1M215.9 249h5.1v2.5"/>
<path d="M219.1 251.5h3.8M242.6 253.2l1.2-1.1 1.3 1.1v13.6h-2.5zM245.1 253.2l1.3-1.1 1.3 1.1v21.3h-2.6zM247.6 258.3l1.3-1.1 1.3 1.1v22h-2.6zM250.2 258.3l1.3-1.1 1.2 1.1v16.6h-2.5zM252.7 243.9h3.8M252.7 241.3h3.8M252.7 246.4h3.8M252.7 249h3.8M252.7 251.5h3.8M252.7 254h3.8M252.7 256.6h3.8"/>
<path d="M256.5 256.4h1.3v.3h-1.3zM256.5 253.9h1.3v.3h-1.3zM256.5 251.4h1.3v.2h-1.3zM256.5 248.8h1.3v.3h-1.3zM256.5 246.3h1.3v.2h-1.3zM256.5 243.7h1.3v.3h-1.3zM256.5 241.2h1.3v.3h-1.3zM260.3 256.4h1.3v.3h-1.3zM260.3 253.9h1.3v.3h-1.3zM260.3 251.4h1.3v.2h-1.3zM260.3 248.8h1.3v.3h-1.3zM260.3 246.3h1.3v.2h-1.3z"/>
<path d="M260.3 243.7h1.3v.3h-1.3zM260.3 241.2h1.3v.3h-1.3zM261.6 243.9h3.8M261.6 241.3h3.8M261.6 246.4h3.8M261.6 249h3.8M261.6 251.5h3.8M261.6 254h3.8M261.6 256.6h3.8M269.1 250.2h13.3v2.6h-13.3l-1.1-1.3zM269.1 252.8h13.2v2.5h-13.2l-1.1-1.3zM269.1 255.3h12.1v2.5h-12.1l-1.1-1.2z"/>
<path d="M269.1 247.7h13.6v2.5h-13.6l-1.1-1.2zM272.4 241.3h7.6M280.7 243.9h7.6M287 242.4h-1l-3 3h-1.1M291.3 242.6h5.1v2.5h-5.1l-1.1-1.2zM294.6 243.3l.4 1.2 .5-1.2M297.2 252.8v1.2M297.2 259.1v1.3M300 253h108v32h-108zM331.5 245.1h5M331.5 240.1h5M337.8 245.1h2.6"/>
<path d="M340.4 243.2v3.9M363.9 247.7h3.8M365.8 245.1v2.6M374 242.6h3.8M375.9 240.1v2.5M384.2 243.9h3.8M386.1 241.3v2.6M395 250.2h3.8M396.9 242.6v7.6M10 260h2M95.9 266.7h19.2l1.1 1.3-1.1 1.3h-19.2zM118.7 271.8v1.3"/>
<path d="M118.7 278.2v3.8M123.8 268h3.8M128.9 268l.6-.6 .7 .6-.7 .6zM128.9 268.6h1.3M135.3 268h2.5M140.4 272.5h12.8l1.1 1.2-1.1 1.3h-12.8zM157.5 273.7h2.5M157.5 268.6h2.5M160 260.4h2.6M164.1 271.4l-3.2 2.1M164.5 260.4h2.5M165.1 271.2h2.5"/>
<path d="M169.4 269.9h16.4v2.6h-16.4l-1.1-1.3zM189.9 271.2h1.2v.2M190.5 271.2l.6 1.3h-1.2zM190.5 266.7v7h10.2v-7M192.4 271.2h1.3v.2M193 271.2l.7 1.3h-1.3zM193 266.7v7M194.9 271.2h1.3v.2M195.6 271.2l.6 1.3h-1.3zM195.6 266.7v10.2M195.6 278.2v2.5M197.5 271.2h1.3v.2"/>
<path d="M198.1 271.2l.7 1.3h-1.3zM198.1 266.7v7M200 271.2h1.3v.2M200.7 271.2l.6 1.3h-1.3zM207.6 271.2h1.3v.2M208.3 271.2l.6 1.3h-1.3zM208.3 266.7v7h10.1v-7M210.2 271.2h1.3v.2M210.8 271.2l.7 1.3h-1.3zM210.8 266.7v7M212.7 271.2h1.3v.2M213.4 271.2l.6 1.3h-1.3z"/>
<path d="M213.4 266.7v10.2M213.4 278.2v2.5M215.3 271.2h1.2v.2M215.9 271.2l.6 1.3h-1.2zM215.9 266.7v7M217.8 271.2h1.3v.2M218.4 271.2l.7 1.3h-1.3zM223.5 273.3v.8h2.6v-.8v.8h2.5v-.8v.8h2.5v-.8v.8h2.6v-.8v.8h2.5v-.8v.8h2.6v-.8v.8h2.5v-.8M223.5 268v1.3M226.1 268v1.3M228.6 268v1.3M231.1 268v1.3"/>
<path d="M233.7 268v1.3M236.2 268v1.3M238.8 268v1.3M241.3 268v1.3M241.3 274.4v2.5M241.3 278.2v2.5M295.3 264.2h3.8M297.2 261.7v2.5M300 278.5h108M300 274.5h108M300 268.5h108M309.1 279.3h.9l-.5 .6 .4 .1v.7l-.2 .1h-.4l-.2-.1"/>
<path d="M310.6 269.1l-1.3 2M316.2 263.7h.6M316.4 263.2v1.3l.4 .2M317.3 263.2v.2M317.3 263.7v1M318.6 263.8l-.4-.1-.3 .3v.4l.2 .2h.5M320 278.5v3M328.9 272.5h.6l.1 .9M329.6 272.8h-.5a.29 .29 0 0 0-.3 .3 .29 .29 0 0 0 .3 .3l.5-.1M330.9 272.5l-.4-.1-.3 .3v.4l.1 .2h.6M330.9 271.9v1.5M331.3 273.6h1.1"/>
<path d="M333.3 272.5l-.4-.1-.2 .2 .1 .2 .5 .2v.3h-.6M334.6 272.5l-.4-.1-.3 .3v.4l.2 .2h.5M335.3 272.6l.2-.2 .4 .1v.9M335.3 271.9v1.5M339.2 279.5l.6-.2 .2 .2 .1 .2-1 1.1h1M342.5 279.5l.6-.2 .2 .2 .1 .2-1 1.1h1M343.8 279.3h1l-.5 .6 .4 .1v.7l-.2 .1h-.4l-.3-.1M384 278.5v6.5M408 260h2M60 285v2M110 285v2M116.8 282h3.8"/>
<path d="M160 285v2M193.7 280.7h3.8M210 285v2M211.5 280.7h3.8M239.4 280.7h3.8M260 285v2M300 281.5h108M310 285v2M332.9 282.7l-.5-.1-.3 .3v.4l.2 .2h.6M332.9 282.1v1.5M333.4 282.6h.5M333.9 282.1l-.3 .2v1.3"/>
<path d="M334.9 282.7l-.3-.1-.2 .2v.2l.5 .2v.3h-.5M336.3 282.6v1.2l-.3 .3-.4-.1M336.3 282.7l-.4-.1-.3 .3v.4l.1 .2h.6M337 283h1.1M338.8 282.5l.4-.4v1.5M338.8 283.6h.8M340.7 280.2h1.2M360 285v2M392.9 282l-1.3 2M394 282.1a.6 .6 0 0 0-.7 .7v.5l.1 .2 .4 .1 .3-.1v-.5l-.1-.2-.4-.1-.3 .3"/>
<circle cx="169.4" cy="39.4" r=".51"/>
<circle cx="173.5" cy="36.9" r=".51"/>
<circle cx="173.5" cy="41.9" r=".51"/>
<circle cx="29.8" cy="64.8" r=".63"/>
<circle cx="45.7" cy="64.8" r=".63"/>
<circle cx="61" cy="64.8" r=".63"/>
<circle cx="76.2" cy="64.8" r=".63"/>
<circle cx="160.7" cy="78.8" r=".63"/>
<circle cx="309.2" cy="63.5" r=".63"/>
<circle cx="184.8" cy="90.2" r=".63"/>
<circle cx="265.9" cy="90.2" r=".51"/>
<circle cx="265.9" cy="95.3" r=".51"/>
<circle cx="270" cy="92.7" r=".51"/>
<circle cx="332.7" cy="91" r=".51"/>
<circle cx="332.7" cy="86.9" r=".51"/>
<circle cx="335.3" cy="91" r=".51"/>
<circle cx="335.3" cy="86.9" r=".51"/>
<circle cx="337.8" cy="86.9" r=".51"/>
<circle cx="337.8" cy="91" r=".51"/>
<circle cx="340.4" cy="91" r=".51"/>
<circle cx="340.4" cy="86.9" r=".51"/>
<circle cx="262.1" cy="109.3" r=".51"/>
<circle cx="262.1" cy="114.3" r=".51"/>
<circle cx="266.2" cy="111.8" r=".51"/>
<circle cx="194.9" cy="120.7" r=".63"/>
<circle cx="210.2" cy="123.2" r=".63"/>
<circle cx="214.6" cy="134.7" r=".63"/>
<circle cx="307.2" cy="134" r=".51"/>
<circle cx="311.3" cy="134" r=".51"/>
<circle cx="144.1" cy="141" r=".63"/>
<circle cx="192.3" cy="142.3" r=".51"/>
<circle cx="192.3" cy="147.4" r=".51"/>
<circle cx="196.3" cy="144.8" r=".51"/>
<circle cx="220.3" cy="151.2" r=".63"/>
<circle cx="263.5" cy="158.8" r=".63"/>
<circle cx="203.8" cy="165.1" r=".63"/>
<circle cx="222.9" cy="167.7" r=".63"/>
<circle cx="298.3" cy="163.9" r=".51"/>
<circle cx="302.4" cy="161.3" r=".51"/>
<circle cx="302.4" cy="166.4" r=".51"/>
<circle cx="191" cy="191.8" r=".51"/>
<circle cx="191" cy="186.7" r=".51"/>
<circle cx="195.1" cy="189.3" r=".51"/>
<circle cx="152.4" cy="228.6" r=".63"/>
<circle cx="288.9" cy="227.4" r=".63"/>
<circle cx="116.8" cy="255.3" r=".63"/>
<circle cx="132.1" cy="252.8" r=".63"/>
<circle cx="167.5" cy="255.3" r=".51"/>
<circle cx="171.6" cy="257.8" r=".51"/>
<circle cx="134.6" cy="268" r=".63"/>
<circle cx="160.5" cy="273.7" r=".51"/>
<circle cx="160.5" cy="268.6" r=".51"/>
<circle cx="164.6" cy="271.2" r=".51"/>
<circle cx="167.5" cy="260.4" r=".51"/>
<circle cx="193" cy="273.7" r=".13"/>
<circle cx="195.6" cy="273.7" r=".13"/>
<circle cx="210.8" cy="273.7" r=".13"/>
<circle cx="213.4" cy="273.7" r=".13"/>
<circle cx="215.9" cy="273.7" r=".13"/>
</g>
<g fill="none" stroke="#840000" stroke-width=".4">
<path d="M390.5 276l.2-.1 .5 .1v1.2M391.3 276.4l-.7 .1a.4 .4 0 0 0-.3 .3 .4 .4 0 0 0 .2 .4l.7-.1M392.3 276.1a.49 .49 0 0 1 .8 .1l-.1 1M392.3 275.9l-.2 1.3M394.9 276a.66 .66 0 0 0-.9 .3l-.1 .6 .1 .2 .2 .1 .6-.1M395 275.2l-.2 2M397.4 276l.2-.1 .6 .1-.1 1.2M398.2 276.4l-.7 .1a.4 .4 0 0 0-.3 .3 .4 .4 0 0 0 .3 .4l.6-.1M399.2 276.1a.49 .49 0 0 1 .9 .1l-.2 1M399.2 275.9l-.1 1.3M401 276l.2-.1 .6 .1-.1 1.2M401.8 276.4l-.6 .1a.4 .4 0 0 0-.4 .3 .4 .4 0 0 0 .3 .4l.6-.1"/>
<path d="M402.9 275.2l-.2 1.8 .3 .2M403.9 276.1a.52 .52 0 0 1 .5-.2 .52 .52 0 0 1 .4 .4l-.1 .6a.55 .55 0 0 1-.5 .4 .55 .55 0 0 1-.5-.4zM406.6 276a.66 .66 0 0 0-1 .3l-.1 .6 .2 .2 .1 .1 .6-.1M406.6 275.9l-.2 1.6a.6 .6 0 0 1-.9 .3"/>
</g>
<path d="M333.2 267.2l.7-.1-.1-.3-.4-.1-.2 .2 .1 .7h.5M335.2 266.8l-.4-.1-.3 .3v.4l.1 .2h.6M335.8 266.2v1.5M336 267.1l.4 .6M336.4 266.7l-.6 .6M337 266.2v.2M337 266.7v1" fill="none" stroke="#840000" stroke-width=".3"/>
<g fill="#fff" stroke="#fff" stroke-width=".18">
<path d="M50.2 20.4h30.4v15.2h-30.4z"/>
<path d="M89.5 20.4h30.5v15.2h-30.5z"/>
<path d="M202.6 16.5h30.4v15.3h-30.4z"/>
<path d="M246.4 16.5h30.5v15.3h-30.5z"/>
<path d="M292.7 17.2h22.9v15.2h-22.9z"/>
</g>
<path d="M202.6 16.5h30.4v15.3h-30.4zM246.4 16.5h30.5v15.3h-30.5zM292.7 17.2h22.9v15.2h-22.9zM50.2 20.4h30.4v15.2h-30.4zM89.5 20.4h30.5v15.2h-30.5z" fill="none" stroke="#840084" stroke-width=".18"/>
<g fill="none" stroke="#848400" stroke-width=".18">
<path d="M50.5 37.1h.5M51.2 36.5h-.7v1.3M51.6 36.5v.1M51.6 36.9v.9M52.2 36.5v1.1l.2 .2M52.8 37.4l.6-.2v-.2l-.4-.1-.2 .2 .1 .6h.5M82.6 37l-.4-.1-.2 .3 .1 .5h.5M82.6 36.5v1.3M82.9 37.9h1M84.6 37l-.3-.1-.2 .2 .1 .2 .4 .1v.3h-.5M85.7 37l-.3-.1-.3 .3 .2 .5h.4M86.3 37.1l.2-.2 .3 .1v.8"/>
<path d="M86.3 36.5v1.3M89.9 37.1h.4M90.5 36.5h-.6v1.3M91 36.5v.1M91 36.9v.9M91.6 36.5v1.1l.2 .2M118.9 37.9h1M120.6 37l-.3-.1-.2 .2 .1 .2 .4 .1v.3h-.5M121.7 37l-.3-.1-.3 .3 .1 .5h.5M122.3 37.1l.2-.2 .3 .1v.8M122.3 36.5v1.3M202.9 33.3h.5"/>
<path d="M203.6 32.7h-.7v1.3M204 32.7v.1M204 33.1v.9M204.6 32.7v1.1l.2 .2M205.2 33.5l.6-.1v-.2l-.4-.1-.2 .2 .1 .6h.5M238.8 33.2h.5l.1 .8M239.4 33.4l-.5 .1-.2 .2 .2 .3 .5-.1M240.5 33.2l-.4-.1-.2 .3 .1 .5h.5M240.5 32.7v1.3M240.8 34.1h1M242.5 33.2l-.3-.1-.2 .2 .1 .2 .4 .1v.3h-.5M243.6 33.2l-.3-.1-.3 .3 .2 .5h.4"/>
<path d="M244.2 33.2l.2-.1 .3 .1v.8M244.2 32.7v1.3M246.8 33.4h.4M247.4 32.7h-.6v1.3M247.9 32.7v.2M247.9 33.2v.8M248.5 32.7v1.1l.1 .2M249.1 33.6l.6-.1-.1-.3h-.4l-.1 .2v.6h.5M284 33.2h.5l.1 .8M284.6 33.5h-.5l-.1 .2 .1 .3h.5M285.7 33.2h-.4l-.2 .2 .1 .6h.5M285.7 32.7v1.3"/>
<path d="M286 34.1h1M287.7 33.2h-.3l-.2 .2 .1 .1 .4 .2v.3h-.5M288.9 33.2h-.4l-.3 .2 .2 .6h.5M289.4 33.3l.2-.1h.3v.8M289.4 32.7v1.3M293.1 33.9h.4M293.7 33.3h-.6v1.3M294.2 33.3v.2M294.2 33.8v.8M294.8 33.3v1.1l.2 .2M295.4 34.2l.6-.1v-.3h-.4l-.2 .1 .1 .6h.5M323.3 33.8h-.4l-.2 .2 .1 .5h.5"/>
<path d="M323.3 33.3v1.3M323.6 34.7h1M325.3 33.8h-.3l-.2 .1 .1 .2 .4 .1v.3h-.5M326.4 33.8h-.3l-.3 .2 .2 .5h.4M327 33.9l.2-.1h.3v.8M327 33.3v1.3"/>
</g>
<g fill="none" stroke="#008484" stroke-width=".18">
<path d="M99.9 18.4h-.3l-.2 .1 .1 .2 .4 .1v.3h-.5M212.8 14.6l.4-.1 .2 .3-.1 .5h-.5M257.3 14.6l-.3-.1-.2 .2 .1 .2 .4 .1v.3h-.5M301.5 15.2l-.4 .2M161.5 49.4v1.2M161.9 49.6v.5l.1 .2h.3l.3-.5 .3-.2 .2 .3v.5M395.2 88.6h-.6v.6l.2-.1h.4l.1 .2-.1 .5-.1 .1-.5-.1M93.4 146.7h.9l-.6 1.3M106.4 146.8l.5-.1 .3 .4-.8 .9h.8M307.8 173.5l-.5-.1-.2 .3 .1 .3 .6 .2v.4l-.2 .1-.5-.1M317 173.8l.4-.4v1.3M317 174.7h.7"/>
<path d="M307.8 187.5l-.5-.1-.2 .2 .1 .4 .6 .2v.4l-.2 .1-.5-.1M317 187.8l.4-.4v1.3M317 188.7h.7M382 188.7l.2-.1a.68 .68 0 0 1 .5 .6 .68 .68 0 0 1-.5 .6l-.3-.4zM383.4 189.1l-.3-.2 .1-.2 .2-.1h.3l.1 .4-.6 .2-.1 .2 .1 .3 .2 .1h.2l.2-.2v-.2l-.2-.3M384.4 188.6a.64 .64 0 0 1 .7 .6 .64 .64 0 0 1-.7 .6zM196.3 206.4h.9l-.6 1.3M209.3 206.5l.5-.1 .2 .3-.8 1h.8M211.7 218.5h-.5M311.9 202.6h.8l-.5 1.2M324.9 202.7l.5-.1 .2 .3-.8 .9h.8M327.3 214.6l-.5 .1"/>
<path d="M327.3 217.2l-.5 .1M211.7 221l-.5 .1M279.4 238.9l.6-.1-.1-.2-.3-.1-.2 .2 .1 .6h.4M287.7 241.5l.6-.2-.1-.2-.4-.1-.1 .2v.6h.5M179.5 275.5h.4M180.1 274.9h-.6v1.3h.6M193.5 274.9l-.4 .1a.86 .86 0 0 0 0 1.2l.4-.1 .1-.4-.2-.3h-.3l-.2 .3M197.2 275.5h.5M197.8 274.9h-.6v1.3h.6M211.3 274.9l-.4 .1a.86 .86 0 0 0 0 1.2l.4-.1 .1-.4-.3-.3h-.2l-.2 .3M282.5 278.1l.6-.1-.1-.2-.3-.1-.2 .2 .1 .6h.4M282.5 271.8l.6-.2-.1-.2-.3-.1-.2 .2 .1 .6h.4"/>
</g>
<g fill="none" stroke="#840000" stroke-width=".25">
<path d="M190.5 35.9h5.1v2h-5.1zM329.6 38.4h5v2h-5zM338.5 39.4l2.5-1.3v2.6zM338.5 38.1v2.6M356.2 38.4h5.1v2h-5.1zM365.1 39.4l2.6-1.3v2.6zM365.1 38.1v2.6M26 56.6h7.7l-3.9 7.6zM41.9 56.6h7.6l-3.8 7.6zM57.1 56.6h7.7l-3.8 7.6zM72.4 56.6h7.6l-3.8 7.6zM157.5 48.3h10.1v10.2h-10.1z"/>
<path d="M189.2 49.6h3.8a3.8 3.8 0 0 1 3.9 3.8 3.8 3.8 0 0 1-3.9 3.8h-3.8zM190.5 40.9h5.1v2.1h-5.1zM205.7 57.2h3.2a5.1 5.1 0 0 1 4.5 3.8 5.2 5.2 0 0 1-4.5 3.8h-3.2a6.6 6.6 0 0 0 0-7.6M285.1 59.7a6.6 6.6 0 0 1 0 7.6M285.7 59.7h3.3a5.1 5.1 0 0 1 4.4 3.8 5.2 5.2 0 0 1-4.4 3.8h-3.2a6.6 6.6 0 0 0-.1-7.6zM301 59.7l7.6 3.8-7.6 3.8zM329.6 46h5v2h-5zM338.5 47l2.5-1.2v2.5zM338.5 45.8v2.5M356.2 46h5.1v2h-5.1zM365.1 47l2.6-1.2v2.5zM365.1 45.8v2.5"/>
<path d="M379.7 50.8h10.2v15.3h-10.2zM392.4 50.8h10.2v15.3h-10.2zM127.3 73.7h2v5.1h-2zM152.4 75l7.6 3.8-7.6 3.8zM167.6 66.1h3.9a3.8 3.8 0 0 1 3.8 3.8 3.8 3.8 0 0 1-3.8 3.8h-3.9zM191.1 68.6h-3.1a6.6 6.6 0 0 1 0 7.6h3.1M191.2 68.6a5.1 5.1 0 0 1 4.4 3.8 5.2 5.2 0 0 1-4.4 3.8M270.5 66.1h3.2a5.1 5.1 0 0 1 4.4 3.8 5.2 5.2 0 0 1-4.4 3.8h-3.2a6.6 6.6 0 0 0 0-7.6zM306.1 71.4h5v2h-5zM312.4 74h5.1v2h-5.1zM318.8 76.5h5v2h-5zM325.1 79h5.1v2.1h-5.1z"/>
<path d="M136.1 81.3h2.1v5.1h-2.1zM152.7 94h2v5.1h-2zM176.5 86.4l7.6 3.8-7.6 3.8zM189.2 99.1h3.2a5.1 5.1 0 0 1 4.4 3.8 5.2 5.2 0 0 1-4.4 3.8h-3.2M189.2 99.1a6.6 6.6 0 0 1 0 7.6M201.3 83.9h-3.2a6.6 6.6 0 0 1 0 7.6h3.2M201.3 83.9a5.1 5.1 0 0 1 4.4 3.8 5.2 5.2 0 0 1-4.4 3.8M279.4 88.9h3.8a3.8 3.8 0 0 1 3.8 3.8 3.8 3.8 0 0 1-3.8 3.9h-3.8zM294.6 91.5h3.2a5.1 5.1 0 0 1 4.5 3.8 5.2 5.2 0 0 1-4.5 3.8h-3.2a6.6 6.6 0 0 0 0-7.6zM330.2 85.1h12.7v7.6h-12.7zM375.9 88.9h10.2v10.2h-10.2zM377.2 95.3l2.5 1.3-2.5 1.2z"/>
<path d="M377.2 90.2l2.5 1.3-2.5 1.2zM379.7 90.2v2.5M379.7 95.3v2.5M382.3 92.7l2.5 1.3-2.5 1.3zM384.8 92.7v2.6M389.9 90.5h5.1v2h-5.1zM391.2 93h5v2h-5zM393.7 95.5h5.1v2.1h-5.1zM186.7 116.9l7.6 3.8-7.6 3.8zM205.1 119.4h-3.2a6.6 6.6 0 0 1 0 7.6h3.2M205.1 119.4a5.1 5.1 0 0 1 4.4 3.8 5.2 5.2 0 0 1-4.4 3.8M210.2 105.4l-3.2 .1a6.6 6.6 0 0 1 0 7.6h3.2"/>
<path d="M210.2 105.4a5.1 5.1 0 0 1 4.4 3.9 5.2 5.2 0 0 1-4.4 3.8M224.8 115.6h3.8a3.8 3.8 0 0 1 3.8 3.8 3.8 3.8 0 0 1-3.8 3.8h-3.8zM251.5 113.3h5v2.1h-5zM285.1 119.4h-3.2a6.6 6.6 0 0 1 0 7.6h3.2M285.1 105.4l-3.2 .1a6.6 6.6 0 0 1 0 7.6h3.2M285.1 119.4a5.1 5.1 0 0 1 4.5 3.8 5.2 5.2 0 0 1-4.5 3.8M285.1 105.4a5.1 5.1 0 0 1 4.5 3.9 5.2 5.2 0 0 1-4.5 3.8M312.4 102.9h3.8a3.8 3.8 0 0 1 3.8 3.8 3.8 3.8 0 0 1-3.8 3.8h-3.8zM373.4 110.5l2.5 1.3-2.5 1.3zM373.4 105.4l2.5 1.3-2.5 1.3zM375.9 105.4v2.6M375.9 110.5v2.6"/>
<path d="M387.3 110.8h5.1v2h-5.1zM387.3 105.7h5.1v2h-5.1zM123.2 138.5h3.8a2.54 2.54 0 0 1 2.5 2.5 2.54 2.54 0 0 1-2.5 2.5h-3.8zM137.2 138.5l6.3 2.5-6.3 2.5zM209.5 130.8l-3.1 .1a6.6 6.6 0 0 1 0 7.6h3.1M209.6 130.8a5.1 5.1 0 0 1 4.4 3.9 5.2 5.2 0 0 1-4.4 3.8M224.8 128.3h3.8a3.8 3.8 0 0 1 3.8 3.8 3.8 3.8 0 0 1-3.8 3.8h-3.8zM252.1 125.8h3.8a3.8 3.8 0 0 1 3.8 3.8 3.8 3.8 0 0 1-3.8 3.8h-3.8zM285.1 133.4h-3.2a6.6 6.6 0 0 1 0 7.6h3.2M285.1 133.4a5.1 5.1 0 0 1 4.5 3.8 5.2 5.2 0 0 1-4.5 3.8M378.5 125.8h10.1v15.2h-10.1zM212.1 147.4l7.6 3.8-7.6 3.8z"/>
<path d="M227.3 152.4h3.2M230.5 144.8h-3.2a6.6 6.6 0 0 1 0 7.6M230.5 144.8a5.1 5.1 0 0 1 4.4 3.8 5.2 5.2 0 0 1-4.4 3.8M247 147.4h-3.2a6.6 6.6 0 0 1 0 7.6h3.2M247 147.4a5.1 5.1 0 0 1 4.5 3.8 5.2 5.2 0 0 1-4.5 3.8M255.3 155l7.6 3.8-7.6 3.8zM309.9 141.3h5.1v2h-5.1zM318.8 141l2.5 1.3-2.5 1.2zM321.3 141v2.5M339.1 158.8h10.1v15.2h-10.1zM353.1 158.8h10.1v15.2h-10.1zM367 158.8h10.2v15.2h-10.2z"/>
<path d="M381 158.8h10.2v15.2h-10.2zM395 158.8h10.1v15.2h-10.1zM195.6 161.3l7.6 3.8-7.6 3.8zM214.6 163.9h3.2a5.1 5.1 0 0 1 4.4 3.8 5.2 5.2 0 0 1-4.4 3.8h-3.2a6.6 6.6 0 0 0 0-7.6zM298.4 175.6h5.1v2h-5.1zM307.3 175.3h10.2v7.6h-10.2zM309.2 178.5h1.3l-.6 1.2zM309.2 179.7h1.3M141 187h5v2h-5zM194.3 197.1h5.1v2.1h-5.1zM204.5 182.9h3.8a3.8 3.8 0 0 1 3.8 3.8 3.8 3.8 0 0 1-3.8 3.8h-3.8zM229.9 185.5h3.8a3.8 3.8 0 0 1 3.8 3.8 3.8 3.8 0 0 1-3.8 3.8h-3.8z"/>
<path d="M264.2 180.4h3.8a3.8 3.8 0 0 1 3.8 3.8 3.8 3.8 0 0 1-3.8 3.8h-3.8zM298.4 189.5h5.1v2.1h-5.1zM307.3 189.3h10.2v7.6h-10.2zM309.2 192.4h1.3l-.6 1.3zM309.2 193.7h1.3M353.1 190.5h10.1v15.3h-10.1zM367 190.5h10.2v15.3h-10.2zM381 190.5h10.2v15.3h-10.2zM395 190.5h10.1v15.3h-10.1zM31.7 204.5l2.6 1.3-2.6 1.2zM31.7 219.7l2.6 1.3-2.6 1.3zM31.7 212.1l2.6 1.3-2.6 1.3z"/>
<path d="M34.3 204.5v2.5M34.3 212.1v2.6M34.3 219.7v2.6M38.1 212.4h5.1v2h-5.1zM38.1 204.8h5.1v2h-5.1zM256.5 219.7h5.1v38.1h-5.1zM294.6 208.6h5.1v2h-5.1zM294.6 213.7h5.1v2h-5.1zM294.6 211.1h5.1v2h-5.1zM294.6 216.2h5.1v2h-5.1zM294.6 218.7h5.1v2.1h-5.1zM31.7 233.7l2.6 1.3-2.6 1.3z"/>
<path d="M31.7 226.7l2.6 1.3-2.6 1.3zM34.3 226.7v2.6M34.3 233.7v2.6M38.1 234h5.1v2h-5.1zM38.1 227h5.1v2h-5.1zM38.1 220h5.1v2h-5.1zM153 228.6l6.4-2.5v5.1zM171.7 230.9l.8-.6 .9-.4h3.8a4.1 4.1 0 0 0 0 5.1h-3.8a3.6 3.6 0 0 1-2.6-2.6l.3-.7zM289.6 227.4l7.6-3.8v7.6zM391.8 227.4h10.2v15.2h-10.2zM121.9 251.5a5.2 5.2 0 0 0-4.4 3.8 5.1 5.1 0 0 0 4.4 3.8M121.9 251.5h3.2a6.6 6.6 0 0 0 0 7.6h-3.2"/>
<path d="M132.7 252.8l7.6-3.8v7.6zM273.7 240.6h5.1v1.5h-5.1zM281.9 243.1h5.1v1.5h-5.1zM296.2 254h2v5.1h-2zM117.7 273.1h2.1v5.1h-2.1zM127.6 265.5l6.4 2.5-6.4 2.5zM188 269.3h15.2v5.1h-15.2zM205.7 269.3h15.3v5.1h-15.3zM222.2 268.6h20.4v6.4h-20.4zM222.8 269.3h1.5v4h-1.5zM225.3 269.3h1.5v4h-1.5zM227.8 269.3h1.6v4h-1.6z"/>
<path d="M230.4 269.3h1.5v4h-1.5zM232.9 269.3h1.5v4h-1.5zM235.5 269.3h1.5v4h-1.5zM238 269.3h1.5v4h-1.5zM240.5 269.3h1.6v4h-1.6z"/>
<circle cx="137.2" cy="73.7" r="2.82"/>
<circle cx="138.4" cy="92.7" r="2.82"/>
<circle cx="374.6" cy="109.3" r="4.6"/>
<circle cx="294.6" cy="237.5" r="1.9"/>
</g>
<path d="M238.8 58.5h15.2v17.7h-15.2zM320 53.4h15.3v12.7h-15.3zM353.1 53.4h20.3v33h-20.3zM87.6 148.6h25.4v45.7h-25.4zM190.5 208.3h25.4v45.7h-25.4zM306.1 204.5h25.4v45.7h-25.4z" fill="none" stroke="#840000" stroke-width=".41"/>
<g fill="#ffffc2" stroke="#ffffc2" stroke-width=".18">
<path d="M284.5 121.9l5.1 1.3a5.2 5.2 0 0 1-4.5 3.8z"/>
<path d="M281.9 127h3.2z"/>
<path d="M281.9 119.4h3.2z"/>
<path d="M281.9 119.4h3.2v7.6h-3.2a6.7 6.7 0 0 0 0-7.6z"/>
<path d="M285.1 119.4a5.1 5.1 0 0 1 4.5 3.8l-5 1.3z"/>
<path d="M255.3 155l7.6 3.8-7.6 3.8z"/>
<path d="M268 180.4a3.8 3.8 0 0 1 3.8 3.8 3.8 3.8 0 0 1-3.8 3.8z"/>
<path d="M264.2 180.4h3.8v7.6h-3.8z"/>
<path d="M284.5 135.8l5.1 1.4a5.2 5.2 0 0 1-4.5 3.8z"/>
<path d="M281.9 141h3.2z"/>
<path d="M281.9 133.4h3.2z"/>
<path d="M281.9 133.4h3.2v7.6h-3.2a6.7 6.7 0 0 0 0-7.6z"/>
<path d="M285.1 133.4a5.1 5.1 0 0 1 4.5 3.8l-5 1.3z"/>
<path d="M229.9 147.3l5 1.3a5.2 5.2 0 0 1-4.4 3.8z"/>
<path d="M227.3 152.4h3.2z"/>
<path d="M227.3 144.8h3.2z"/>
<path d="M227.3 144.8h3.2v7.6h-3.2a6.7 6.7 0 0 0 0-7.6z"/>
<path d="M230.5 144.8a5.1 5.1 0 0 1 4.4 3.8l-4.9 1.3z"/>
<path d="M228.6 115.6a3.8 3.8 0 0 1 3.8 3.8 3.8 3.8 0 0 1-3.8 3.8z"/>
<path d="M224.8 115.6h3.8v7.6h-3.8z"/>
<path d="M307.3 175.3h10.2v7.6h-10.2z"/>
<path d="M307.3 189.3h10.2v7.6h-10.2z"/>
<path d="M301 59.7l7.6 3.8-7.6 3.8z"/>
<path d="M255.9 125.8a3.8 3.8 0 0 1 3.8 3.8 3.8 3.8 0 0 1-3.8 3.8z"/>
<path d="M252.1 125.8h3.8v7.6h-3.8z"/>
<path d="M378.5 125.8h10.1v15.2h-10.1z"/>
<path d="M297.2 93.9l5.1 1.4a5.2 5.2 0 0 1-4.5 3.8z"/>
<path d="M294.6 99.1h3.2z"/>
<path d="M294.6 91.5h3.2z"/>
<path d="M294.6 91.5h3.2v7.6h-3.2a6.7 6.7 0 0 0 0-7.6z"/>
<path d="M297.8 91.5a5.1 5.1 0 0 1 4.5 3.8l-5 1.3z"/>
<path d="M283.2 88.9a3.8 3.8 0 0 1 3.8 3.8 3.8 3.8 0 0 1-3.8 3.9z"/>
<path d="M279.4 88.9h3.8v7.7h-3.8z"/>
<path d="M233.7 185.5a3.8 3.8 0 0 1 3.8 3.8 3.8 3.8 0 0 1-3.8 3.8z"/>
<path d="M229.9 185.5h3.8v7.6h-3.8z"/>
<path d="M367 158.8h10.2v15.2h-10.2z"/>
<path d="M395 158.8h10.1v15.2h-10.1z"/>
<path d="M246.4 149.8l5.1 1.4a5.2 5.2 0 0 1-4.5 3.8z"/>
<path d="M243.8 155h3.2z"/>
<path d="M243.8 147.4h3.2z"/>
<path d="M243.8 147.4h3.2v7.6h-3.2a6.7 6.7 0 0 0 0-7.6z"/>
<path d="M247 147.4a5.1 5.1 0 0 1 4.5 3.8l-5 1.3z"/>
<path d="M273.1 68.5l5 1.4a5.2 5.2 0 0 1-4.4 3.8z"/>
<path d="M270.5 73.7h3.2z"/>
<path d="M270.5 66.1h3.2z"/>
<path d="M270.5 66.1h3.2v7.6h-3.2a6.7 6.7 0 0 0 0-7.6z"/>
<path d="M273.7 66.1a5.1 5.1 0 0 1 4.4 3.8l-4.9 1.3z"/>
<path d="M288.4 62.2l5 1.3a5.2 5.2 0 0 1-4.4 3.8z"/>
<path d="M285.7 67.3h3.2z"/>
<path d="M285.7 59.7h3.2z"/>
<path d="M285.7 59.7h3.2v7.6h-3.2a6.7 6.7 0 0 0 0-7.6z"/>
<path d="M289 59.7a5.1 5.1 0 0 1 4.4 3.8l-5 1.3z"/>
<path d="M228.6 128.3a3.8 3.8 0 0 1 3.8 3.8 3.8 3.8 0 0 1-3.8 3.8z"/>
<path d="M224.8 128.3h3.8v7.6h-3.8z"/>
<path d="M330.2 85.1h12.7v7.6h-12.7z"/>
<path d="M316.2 102.9a3.8 3.8 0 0 1 3.8 3.8 3.8 3.8 0 0 1-3.8 3.8z"/>
<path d="M312.4 102.9h3.8v7.6h-3.8z"/>
<path d="M284.5 107.9l5.1 1.4a5.2 5.2 0 0 1-4.5 3.8z"/>
<path d="M281.9 113.1h3.2z"/>
<path d="M281.9 105.4h3.2z"/>
<path d="M281.9 105.4h3.2v7.7h-3.2a6.7 6.7 0 0 0 0-7.7z"/>
<path d="M285.1 105.4a5.1 5.1 0 0 1 4.5 3.9l-5 1.3z"/>
<path d="M176.5 86.4l7.6 3.8-7.6 3.8z"/>
<path d="M152.4 75l7.6 3.8-7.6 3.8z"/>
<path d="M195.6 161.3l7.6 3.8-7.6 3.8z"/>
<path d="M212.1 147.4l7.6 3.8-7.6 3.8z"/>
<path d="M157.5 48.3h10.1v10.2h-10.1z"/>
<path d="M256.5 219.7h5.1v38.1h-5.1z"/>
<path d="M208.3 59.6l5.1 1.4a5.2 5.2 0 0 1-4.5 3.8z"/>
<path d="M205.7 64.8h3.2z"/>
<path d="M205.7 57.2h3.2z"/>
<path d="M205.7 57.2h3.2v7.6h-3.2a6.7 6.7 0 0 0 0-7.6z"/>
<path d="M208.9 57.2a5.1 5.1 0 0 1 4.5 3.8l-5 1.3z"/>
<path d="M204.5 121.9l5 1.3a5.2 5.2 0 0 1-4.4 3.8z"/>
<path d="M201.9 127h3.2z"/>
<path d="M201.9 119.4h3.2z"/>
<path d="M201.9 119.4h3.2v7.6h-3.2a6.7 6.7 0 0 0 0-7.6z"/>
<path d="M205.1 119.4a5.1 5.1 0 0 1 4.4 3.8l-4.9 1.3z"/>
<path d="M193 49.6a3.8 3.8 0 0 1 3.9 3.8 3.8 3.8 0 0 1-3.9 3.8z"/>
<path d="M189.2 49.6h3.8v7.6h-3.8z"/>
<path d="M222.2 268.6h20.4v6.4h-20.4z"/>
<path d="M209.6 107.9l5 1.4a5.2 5.2 0 0 1-4.4 3.8z"/>
<path d="M207 113.1h3.2z"/>
<path d="M207 105.4h3.2z"/>
<path d="M207 105.4h3.2v7.7h-3.2a6.7 6.7 0 0 0 0-7.7z"/>
<path d="M210.2 105.4a5.1 5.1 0 0 1 4.4 3.9l-4.9 1.3z"/>
<path d="M191.8 101.6l5 1.3a5.2 5.2 0 0 1-4.4 3.8z"/>
<path d="M189.2 106.7h3.2z"/>
<path d="M189.2 99.1h3.2z"/>
<path d="M189.2 99.1h3.2v7.6h-3.2a6.7 6.7 0 0 0 0-7.6z"/>
<path d="M192.4 99.1a5.1 5.1 0 0 1 4.4 3.8l-4.9 1.3z"/>
<path d="M173.4 229.9h3.8z"/>
<path d="M173.4 235h3.8z"/>
<path d="M205.7 269.3h15.3v5.1h-15.3z"/>
<path d="M188 269.3h15.2v5.1h-15.2z"/>
<path d="M132.7 252.8l7.6-3.8v7.6z"/>
<path d="M200.7 86.3l5 1.4a5.2 5.2 0 0 1-4.4 3.8z"/>
<path d="M198.1 91.5h3.2z"/>
<path d="M198.1 83.9h3.2z"/>
<path d="M198.1 83.9h3.2v7.6h-3.2a6.7 6.7 0 0 0 0-7.6z"/>
<path d="M201.3 83.9a5.1 5.1 0 0 1 4.4 3.8l-4.9 1.3z"/>
<path d="M190.6 71.1l5 1.3a5.2 5.2 0 0 1-4.4 3.8z"/>
<path d="M188 76.2h3.1z"/>
<path d="M188 68.6h3.1z"/>
<path d="M188 68.6h3.1v7.6h-3.1a6.7 6.7 0 0 0 0-7.6z"/>
<path d="M191.2 68.6a5.1 5.1 0 0 1 4.4 3.8l-5 1.3z"/>
<path d="M190.5 208.3h25.4v45.7h-25.4z"/>
<path d="M217.2 166.3l5 1.4a5.2 5.2 0 0 1-4.4 3.8z"/>
<path d="M214.6 171.5h3.2z"/>
<path d="M214.6 163.9h3.2z"/>
<path d="M214.6 163.9h3.2v7.6h-3.2a6.7 6.7 0 0 0 0-7.6z"/>
<path d="M217.8 163.9a5.1 5.1 0 0 1 4.4 3.8l-4.9 1.3z"/>
<path d="M171.5 66.1a3.8 3.8 0 0 1 3.8 3.8 3.8 3.8 0 0 1-3.8 3.8z"/>
<path d="M167.6 66.1h3.8v7.6h-3.8z"/>
<path d="M209 133.3l5 1.4a5.2 5.2 0 0 1-4.4 3.8z"/>
<path d="M206.4 138.5h3.1z"/>
<path d="M206.4 130.8h3.1z"/>
<path d="M206.4 130.8h3.1v7.7h-3.1a6.7 6.7 0 0 0 0-7.7z"/>
<path d="M209.6 130.8a5.1 5.1 0 0 1 4.4 3.9l-5 1.3z"/>
<path d="M381 190.5h10.2v15.3h-10.2z"/>
<path d="M367 190.5h10.2v15.3h-10.2z"/>
<path d="M375.9 88.9h10.2v10.2h-10.2z"/>
<path d="M395 190.5h10.1v15.3h-10.1z"/>
<path d="M391.8 227.4h10.2v15.2h-10.2z"/>
<path d="M339.1 158.8h10.1v15.2h-10.1z"/>
<path d="M186.7 116.9l7.6 3.8-7.6 3.8z"/>
<path d="M208.3 182.9a3.8 3.8 0 0 1 3.8 3.8 3.8 3.8 0 0 1-3.8 3.8z"/>
<path d="M204.5 182.9h3.8v7.6h-3.8z"/>
<path d="M353.1 190.5h10.1v15.3h-10.1z"/>
<path d="M392.4 50.8h10.2v15.3h-10.2z"/>
<path d="M379.7 50.8h10.2v15.3h-10.2z"/>
<path d="M118.7 253.1a5.2 5.2 0 0 1 3.2-1.6l.6 5.2-5-1.4 .4-1.1z"/>
<path d="M121.9 251.5h3.2z"/>
<path d="M121.9 259.1h3.2z"/>
<path d="M121.9 251.5h3.2a6.7 6.7 0 0 0 0 7.6h-3.2z"/>
<path d="M117.5 255.3l5-1.3-.6 5.1a5.1 5.1 0 0 1-4.4-3.8z"/>
<path d="M26 56.6h7.7l-3.9 7.6z"/>
<path d="M57.1 56.6h7.7l-3.8 7.6z"/>
<path d="M41.9 56.6h7.6l-3.8 7.6z"/>
<path d="M381 158.8h10.2v15.2h-10.2z"/>
<path d="M72.4 56.6h7.6l-3.8 7.6z"/>
<path d="M87.6 148.6h25.4v45.7h-25.4z"/>
<path d="M306.1 204.5h25.4v45.7h-25.4z"/>
<path d="M289.6 227.4l7.6-3.8v7.6z"/>
<path d="M353.1 158.8h10.1v15.2h-10.1z"/>
<circle cx="374.6" cy="109.3" r="4.6"/>
</g>
<g fill="none" stroke="#840000" stroke-width=".51">
<path d="M337.1 26.2h4M337.1 24.7h4M345.9 26.2h4.1M345.9 24.7h4.1M354.8 26.2h4.1M354.8 24.7h4.1M365 26.2h4.1M365 24.7h4.1M375.2 26.2h4M375.2 24.7h4M386.6 26.2h4.1M386.6 24.7h4.1"/>
<path d="M398 26.2h4.1M398 24.7h4.1M135.3 74.3h3.8M139.1 90.8v3.9M315 177.2v3.8M315 191.2v3.8M293.5 237.5h2.3M294.6 236.4v2.3"/>
</g>
<g fill="#840000" stroke="#840000" stroke-width=".18">
<path d="M315 179.7l1.9 1.9z"/>
<path d="M315.5 180.8l.5-.6 .5 1.1z"/>
<path d="M315 193.7l1.9 1.9z"/>
<path d="M315.5 194.7l.5-.5 .5 1z"/>
<path d="M134.9 73.2l.5-.5 .5 1z"/>
<path d="M137.9 94l.5 .5-1 .5z"/>
<path d="M322.8 147.9h4.6v.5h-4.6z"/>
<circle cx="241.3" cy="274.1" r=".25"/>
<circle cx="238.8" cy="274.1" r=".25"/>
<circle cx="236.2" cy="274.1" r=".25"/>
<circle cx="233.7" cy="274.1" r=".25"/>
<circle cx="231.1" cy="274.1" r=".25"/>
<circle cx="228.6" cy="274.1" r=".25"/>
<circle cx="226.1" cy="274.1" r=".25"/>
</g>
<g fill="none" stroke="#840000" stroke-width="1.3">
<circle cx="268" cy="276.3" r="1.27"/>
<circle cx="268" cy="269.9" r="1.27"/>
</g>
<g fill="none" stroke="#0000c2" stroke-width=".18">
<path d="M173.4 13.5v1.2M173.8 13.5h.7M174.2 13.5v1.2M175.7 13.6a.6 .6 0 0 0-.9 .4 .6 .6 0 0 0 .6 .7l.3-.1M176.2 13.5v1.2M176.2 14.1h.7M176.9 13.5v1.2M177.5 13.9v.2M177.6 14.7l-.1 .2M192.5 16.1h.5M193.1 15.5h-.6v1.3h.6M195.4 15.5v1.3l-.7-1.3v1.3"/>
<path d="M196 15.5v1.3M197.3 15.5v1.3l-.7-1.3v1.3M197.9 15.5v1.3M199.2 15.6a.59 .59 0 0 0-.7 .5 .59 .59 0 0 0 .7 .6l.1-.5h-.3M199.8 15.5v1.3M46 265.3l.3-.1 .3 .2v.4l-.3 .2h-.3l-.1-.2zM47.9 265.2h.5M48.1 264.8v1.1l.3 .1M48.9 265.3l.3-.1 .2 .2v.4l-.2 .2h-.3l-.1-.2zM50.6 263.3l.2-.1h.3l.1 .8M50.9 265.4h.6l.2-.2-.1-.3-.7-.1v1.2M52.8 263.4l.6-.1 .1-.1-.1-.3-.6-.2v1.3"/>
<path d="M52.9 264.9a.6 .6 0 0 0-.8 .4 .6 .6 0 0 0 .6 .7l.2-.1M54.7 262.9a.6 .6 0 0 0-.8 .4 .6 .6 0 0 0 .6 .7l.2-.1M62.8 269.4l.2-.1 .3 .1v.7M62.8 269.3v.8M63.8 269.3h.4M63.9 268.9v1.1l.3 .1M64.7 269.3v.8M65 269.3l-.3 .2M65.5 269.4l.3-.1 .3 .2v.4l-.3 .2h-.3l-.1-.2zM66.6 268.9v1.1l.2 .1M68.2 269.5h.6l.2-.2-.1-.3-.7-.1v1.2M69.7 268.9v1.2"/>
<path d="M70.7 268.9v1.2M77.4 267.4l.1-.2 .3 .1 .1 .8M79.5 266.8v.1M79.5 267.2v.9M80.5 267.3l-.3-.1-.2 .2 .1 .2 .4 .1v.3h-.5M82.1 267.3h.5v.8M82.6 267.5l-.4 .1-.2 .2 .2 .3 .4-.1M83.8 267.3l-.4-.1-.2 .3 .1 .5h.5M84.1 267.2h.5M84.3 266.8v1.1l.3 .2M85 266.8v.1M85 267.2v.9"/>
<path d="M85.5 267.2l.3 .9 .3-.9M86.6 267.7l.6-.2-.1-.2-.4-.1-.1 .2v.6h.5M176.6 279.5h-.4l-.2 .2 .1 .5h.5M176.6 279v1.3M177.6 279.5h-.3l-.1 .1v.2l.4 .1v.3h-.4M178.2 279.6l.2-.1 .4 .1v.5l-.1 .1-.3 .1-.2-.1zM179.4 279v1.1l.2 .2M180.6 279.5h-.4l-.2 .2 .1 .5h.5M180.6 279v1.3M181.1 279.9l.6-.1v-.3h-.4l-.2 .1 .1 .6h.5M182.3 279.5v.8M182.7 279.5l-.4 .2"/>
<path d="M183.1 279v.1M183.1 279.5v.8M183.7 279.6l.2-.1h.3v.8M183.7 279.5v.8M185.4 279.5v1l-.3 .2h-.3M185.4 279.5h-.4l-.2 .2 .1 .5h.5M174.5 282.2h.6l.1-.2v-.3l-.7-.1v1.2M175.8 281.7l.2-.1a.68 .68 0 0 1 .4 .6 .68 .68 0 0 1-.4 .6l-.3-.4zM177 282.7v.1M178.2 282.1l-.2 .3-.4-.1-.1-.2v-.3l.3-.2h.2l.2 .2a.84 .84 0 0 1-.3 1h-.3M179.4 281.6h-.6l-.1 .6 .2-.1h.4l.1 .2v.4l-.2 .1-.5-.1M180 282.1l.2-.1 .3 .1v.7"/>
<path d="M180 282v.8M180.5 282.2l.2-.2 .3 .1 .1 .7M181.7 282.1l.2-.1 .3 .1v.7M181.7 282v.8M182.2 282.2l.2-.2 .3 .1 .1 .7"/>
</g>
<g fill="none" stroke="#008400" stroke-width=".18">
<path d="M162.6 39.4h3.8M162.6 38.1v7.7M176.5 36.9h12.7M196.8 36.9h1.3M339.1 29.2v.7h60.9M343.5 39.4h6.4M348 29.2v.7M356.9 29.2v.7M367 29.2v.7M370.2 39.4h6.4M377.2 20.4v1.2M377.2 29.2v.7"/>
<path d="M388.6 20.4v1.2M388.6 29.2v.7M400 20.4v1.2h-60.9M400 29.2v2M149.9 53.4h5M154.9 50.8h-8.9v21.6h-3.8M170.2 50.8h15.2M175.3 55.9h10.1M176.5 41.9h12.7M196.8 41.9h1.3M200.7 53.4h1.2v5.1M219.1 52.1h-1.9v43.2h45.7"/>
<path d="M308.6 55.9h6.4M340.4 55.9h7.6M340.4 58.5h7.6M343.5 47h6.4M370.2 47h6.4M384.8 44.5v1.3M397.5 44.5v1.3M128.3 69.9v2.5h3.8M143.5 63.5h2.5M146 67.3h17.8M148.6 78.8v189.2h-10.8M153.7 72.4h10.1"/>
<path d="M162.6 61v1.9h-3.2M163.8 78.8h49.6v19h77.4M179.1 69.9h5M184.1 75h-17.7v30.4h19M201.9 63.5v8.9h-2.5M217.2 61h16.5M218.4 73.7h15.3M227.3 71.2h6.4M229.9 67.3h3.8M259.1 61h22.8M262.9 61v29.2M266.7 67.3h-6.4v11.5h-43.1"/>
<path d="M266.7 72.4v8.9h-53.3M266.7 78.1h1.9M281.9 66.1v6.3M302.3 72.4h2.5M302.3 75h8.8M302.3 77.5h15.2M302.3 71.8v8.2h21.5M332.7 72.4v8.9M335.3 75v6.3M337.8 77.5v3.8M340.4 61h7.6M340.4 63.5h7.6"/>
<path d="M345.4 78.8h2.6M348 66.1h-11.5v6.3h-24.1M348 68.6h-10.2v6.4h-19M348 71.2h-8.9v6.3h-14M348 73.7h-7.6v7.6M384.8 71.2v1.2M397.5 71.2v1.2M128.3 80h8.9M144.8 92.7h8.9M172.7 90.2h-3.8v10.2h12.7v113h3.8M188 90.2h6.3M194.3 85.1h-43.2v68.6h-33"/>
<path d="M273 92.7v2.6h2.6M294.6 86.4h-20.3v3.8h1.3M306.1 95.3v5.1h-30.5v6.3h2.5M308.6 83.9v20.3M309.9 83.9h-99.1v3.8h-1.3M331.5 80h8.9M332.7 96.6h7.7M345.4 81.3h2.6M346.7 83.9h1.3M348 91.5h25.4M354.3 94h19.1M372.1 96.6h1.3"/>
<path d="M378.5 81.3h19M388.6 94h1.3M388.6 96.6h3.8M396.2 91.5h3.8v5.1M397.5 94h2.5M153.7 100.4v22.8h15.2v102.9h16.5M185.4 100.4h-2.5v-6.4h27.9v6.4h62.2v11.4M185.4 111.8h17.8M200.7 102.9h1.2v3.8h1.3M218.4 109.3h1.3v7.6h1.3M236.2 119.4h7.6v7.6h4.5M248.9 114.3h1.3"/>
<path d="M251.5 109.3h7.6M257.8 114.3h1.3M269.2 111.8h8.9M293.4 109.3h15.2M323.8 106.7h1.3v7.6h-49.5v6.4h2.5M349.2 106.7h17.8M349.2 111.8h17.8M382.3 106.7h3.8M382.3 111.8h3.8M383.5 119.4v1.3M99.1 139.7h20.3M138.4 130.8h15.3v44.5h123.2v8.9h-1.3"/>
<path d="M182.9 137.2h19.7M182.9 120.7h-26.7v38.1h-38.1M198.1 125.8h-26.7v97.8h14M213.4 123.2v4.5h-10.8v4.4M221 122h-5.1v-7.7h-52.1v63.5h77.5v11.5M221 134.7h-1.3v10.1h-20.3M221 129.6h-3.2v5.1M236.2 132.1h12.1M263.5 129.6h2.6v9.5h-43.9v7h1.3M278.1 139.7h-1.2v33.1h-100.4v45.7h8.9M278.1 125.8h-3.8v33h-7.6M293.4 137.2v5.1h15.2"/>
<path d="M293.4 123.2h1.2v5.1h-19v6.4h2.5M301.6 134h2.6M314.3 134h10.8v9.5M80 151.2v2.5h2.5M82.5 158.8h-2.5v2.5h2.5M119.4 142.3h-1.3v8.9h35.6M147.3 141h1.3M186.7 147.4h2.5M208.3 151.2h-49.6v12.7h-40.6M238.8 148.6h1.2M240 153.7h-22.8v3.8h-43.2v63.5h11.4M251.5 158.8h-90.2v10.1h-43.2"/>
<path d="M255.3 151.2h15.2M323.8 142.3h5.1M325.1 151.2v1.2M344.2 153.7h55.8M383.5 146.1v1.3M72.4 176.6h10.1M72.4 171.5h10.1M72.4 166.4h10.1M191.8 165.1h-26.7v6.4h-47M207 165.1h3.8M210.8 170.2h-44.4v62.2h.6M226.1 167.7h19"/>
<path d="M294 163.9h1.3M297.2 176.6h-3.8v27.9h-26.7v16.5h-1.3M305.4 161.3h1.3M320 176.6h1.9M344.2 179.1h55.8M358.1 176.6v2.5M72.4 181.6h10.1M80 189.3h2.5M82.5 184.2h-8.8v2.5h-1.3M134.6 185.5v2.5h5.1M147.3 188h1.3M186.1 186.7h1.9"/>
<path d="M191.8 198.2h1.2M198.1 189.3h2.6v8.9M200.7 184.2h-21.6v31.7h6.3M215.9 186.7h10.2M224.8 191.8h1.3M241.3 186.7h19M248.9 181.6h11.4M297.2 190.5h-2.6v16.5h-26.6v16.6h-2.6M303.5 181.6h1.3M303.5 195.6h1.3M320 181.6h2.6M320 195.6h1.3"/>
<path d="M320 190.5h2.6M358.1 185.5h44.5M17.8 213.4h11.4M17.8 205.8h11.4M44.4 205.8h3.9v32.4M44.4 213.4h3.9M228.6 218.5h-6.4v2.5h-1.2M293.4 217.2h-20.4v16.5h-7.6M293.4 219.7h-19.1v16.6h-8.9M293.4 214.7h-21.6v16.5h-6.4M293.4 212.1h-22.9v16.5h-5.1M293.4 209.6h-24.2v16.5h-3.8"/>
<path d="M336.5 214.7h5.8M336.5 209.6h2M338.5 214.7v2.5h-2M358.1 210.9h41.9M12.1 228h17.1M13.3 235h15.9M15.2 221h14M44.4 235h3.9M44.4 221h3.9M44.4 228h3.9M148.6 228.6h.6M163.2 228.6h22.2"/>
<path d="M181 233.7h5.7v24.1h-12.1M181 231.2h4.4M221 238.8h2.5v2.5h29.2M221 236.3h31.7M221 233.7h31.7M221 228.6h31.7M221 231.2h31.7M221 226.1h31.7M231.1 236.3v30.4M233.7 233.7v33M236.2 231.2v35.5M238.8 228.6v38.1"/>
<path d="M241.3 226.1v40.6M250.2 238.8h2.5M264.2 238.8h1.2M285.7 227.4h-9.5v3.8h3.2M336.5 227.4h25.4M336.5 229.9h25.4M336.5 224.8h25.4M336.5 222.3h25.4M336.5 235h1.3v2.5h-1.3M336.5 232.4h25.4M386.1 237.5v3.8M396.9 221v1.3h-31.1"/>
<path d="M112.4 255.3h1.3M128.9 257.8v3.2h-10.2v10.8M146 246.4v6.4h-1.9M160.7 255.3h3.8M221 241.3h1.2v2.6h30.5M221 243.9v2.5h31.7M223.5 246.4v20.3M226.1 243.9v22.8M228.6 241.3v25.4M236.2 259.1h-35.5v7.6M238.8 257.8h-40.7v8.9M241.3 256.6h-45.7v10.1"/>
<path d="M252.7 249h-8.9v3.1M252.7 251.5h-6.3v.6M252.7 256.6h-1.2v.6M252.7 254h-3.8v3.2M265.4 241.3h7M265.4 251.5h2.6M265.4 246.4h31.8v6.4M265.4 249h2.6M265.4 243.9h15.3M265.4 256.6h2.6M265.4 254h2.6M288.3 243.9h1.9"/>
<path d="M294.6 240.7v.6h-14.6M336.5 240.1h7.7v11.4h-47M336.5 245.1h1.3M365.8 243.9v1.2M116.2 268h7.6M154.3 273.7h3.2M162.6 260.4h1.9M167.6 271.2h.7M195.6 276.9v1.3M213.4 276.9v1.3M223.5 265.5h-5.1v1.2M226.1 264.2h-10.2v2.5"/>
<path d="M228.6 262.9h-15.2v3.8M231.1 261.7h-20.3v5M233.7 260.4h-25.4v6.3M241.3 276.9v1.3M297.2 260.4v1.3"/>
</g>
<g fill="none" stroke="#000084" stroke-width=".18">
<path d="M262.3 66.7l1.2 1.3M263.5 66.7l-1.2 1.3M212.8 83.2l1.2 1.3M214 83.2l-1.2 1.3M216.6 80.7l1.2 1.2M216.6 83.2l1.2 1.3M217.8 80.7l-1.2 1.2M217.8 83.2l-1.2 1.3M262.3 80.7l1.2 1.2M262.3 83.2l1.2 1.3M263.5 80.7l-1.2 1.2M263.5 83.2l-1.2 1.3"/>
<path d="M181 104.8l1.2 1.3M182.2 104.8l-1.2 1.3M168.3 120.1l1.2 1.2M169.5 120.1l-1.2 1.2M181 120.1l1.2 1.2M181 125.2l1.2 1.2M182.2 125.2l-1.2 1.2M182.2 120.1l-1.2 1.2M148 153.1l1.2 1.2M148 158.2l1.2 1.2M149.2 153.1l-1.2 1.2M149.2 158.2l-1.2 1.2"/>
<path d="M148 163.3l1.2 1.2M148 168.3l1.2 1.3M148 170.9l1.2 1.2M149.2 163.3l-1.2 1.2M149.2 168.3l-1.2 1.3M149.2 170.9l-1.2 1.2M165.8 228l1.2 1.2M167 228l-1.2 1.2"/>
</g>
<g fill="#008400" stroke="#008400" stroke-width=".18">
<circle cx="200.7" cy="189.3" r=".46"/>
<circle cx="231.1" cy="261.7" r=".46"/>
<circle cx="233.7" cy="260.4" r=".46"/>
<circle cx="223.5" cy="265.5" r=".46"/>
<circle cx="226.1" cy="264.2" r=".46"/>
<circle cx="80" cy="158.8" r=".46"/>
<circle cx="48.3" cy="213.4" r=".46"/>
<circle cx="148.6" cy="188" r=".46"/>
<circle cx="48.3" cy="235" r=".46"/>
<circle cx="118.7" cy="268" r=".46"/>
<circle cx="48.3" cy="221" r=".46"/>
<circle cx="148.6" cy="228.6" r=".46"/>
<circle cx="48.3" cy="228" r=".46"/>
<circle cx="302.3" cy="75" r=".46"/>
<circle cx="302.3" cy="77.5" r=".46"/>
<circle cx="337.8" cy="96.6" r=".46"/>
<circle cx="335.3" cy="96.6" r=".46"/>
<circle cx="337.8" cy="77.5" r=".46"/>
<circle cx="348" cy="21.6" r=".46"/>
<circle cx="348" cy="29.9" r=".46"/>
<circle cx="281.9" cy="69.9" r=".46"/>
<circle cx="266.7" cy="78.1" r=".46"/>
<circle cx="356.9" cy="29.9" r=".46"/>
<circle cx="367" cy="21.6" r=".46"/>
<circle cx="356.9" cy="21.6" r=".46"/>
<circle cx="367" cy="29.9" r=".46"/>
<circle cx="388.6" cy="21.6" r=".46"/>
<circle cx="388.6" cy="29.9" r=".46"/>
<circle cx="377.2" cy="21.6" r=".46"/>
<circle cx="400" cy="29.9" r=".46"/>
<circle cx="377.2" cy="29.9" r=".46"/>
<circle cx="400" cy="21.6" r=".46"/>
<circle cx="332.7" cy="72.4" r=".46"/>
<circle cx="335.3" cy="75" r=".46"/>
<circle cx="302.3" cy="72.4" r=".46"/>
<circle cx="308.6" cy="83.9" r=".46"/>
<circle cx="217.2" cy="78.8" r=".46"/>
<circle cx="273" cy="111.8" r=".46"/>
<circle cx="340.4" cy="96.6" r=".46"/>
<circle cx="340.4" cy="80" r=".46"/>
<circle cx="400" cy="91.5" r=".46"/>
<circle cx="146" cy="63.5" r=".46"/>
<circle cx="148.6" cy="141" r=".46"/>
<circle cx="128.3" cy="72.4" r=".46"/>
<circle cx="137.2" cy="80" r=".46"/>
<circle cx="236.2" cy="259.1" r=".46"/>
<circle cx="238.8" cy="257.8" r=".46"/>
<circle cx="297.2" cy="251.5" r=".46"/>
<circle cx="241.3" cy="226.1" r=".46"/>
<circle cx="241.3" cy="256.6" r=".46"/>
<circle cx="236.2" cy="231.2" r=".46"/>
<circle cx="223.5" cy="246.4" r=".46"/>
<circle cx="228.6" cy="262.9" r=".46"/>
<circle cx="213.4" cy="81.3" r=".46"/>
<circle cx="146" cy="67.3" r=".46"/>
<circle cx="166.4" cy="78.8" r=".46"/>
<circle cx="162.6" cy="39.4" r=".46"/>
<circle cx="372.1" cy="185.5" r=".46"/>
<circle cx="372.1" cy="179.1" r=".46"/>
<circle cx="344.2" cy="179.1" r=".46"/>
<circle cx="381" cy="210.9" r=".46"/>
<circle cx="372.1" cy="210.9" r=".46"/>
<circle cx="386.1" cy="179.1" r=".46"/>
<circle cx="386.1" cy="185.5" r=".46"/>
<circle cx="386.1" cy="210.9" r=".46"/>
<circle cx="375.9" cy="222.3" r=".46"/>
<circle cx="386.1" cy="222.3" r=".46"/>
<circle cx="400" cy="185.5" r=".46"/>
<circle cx="396.9" cy="222.3" r=".46"/>
<circle cx="338.5" cy="214.7" r=".46"/>
<circle cx="241.3" cy="186.7" r=".46"/>
<circle cx="238.8" cy="228.6" r=".46"/>
<circle cx="386.1" cy="153.7" r=".46"/>
<circle cx="358.1" cy="153.7" r=".46"/>
<circle cx="358.1" cy="179.1" r=".46"/>
<circle cx="372.1" cy="153.7" r=".46"/>
<circle cx="400" cy="94" r=".46"/>
<circle cx="337.8" cy="237.5" r=".46"/>
<circle cx="325.1" cy="142.3" r=".46"/>
</g>
<use href="#words"/>
</svg>
